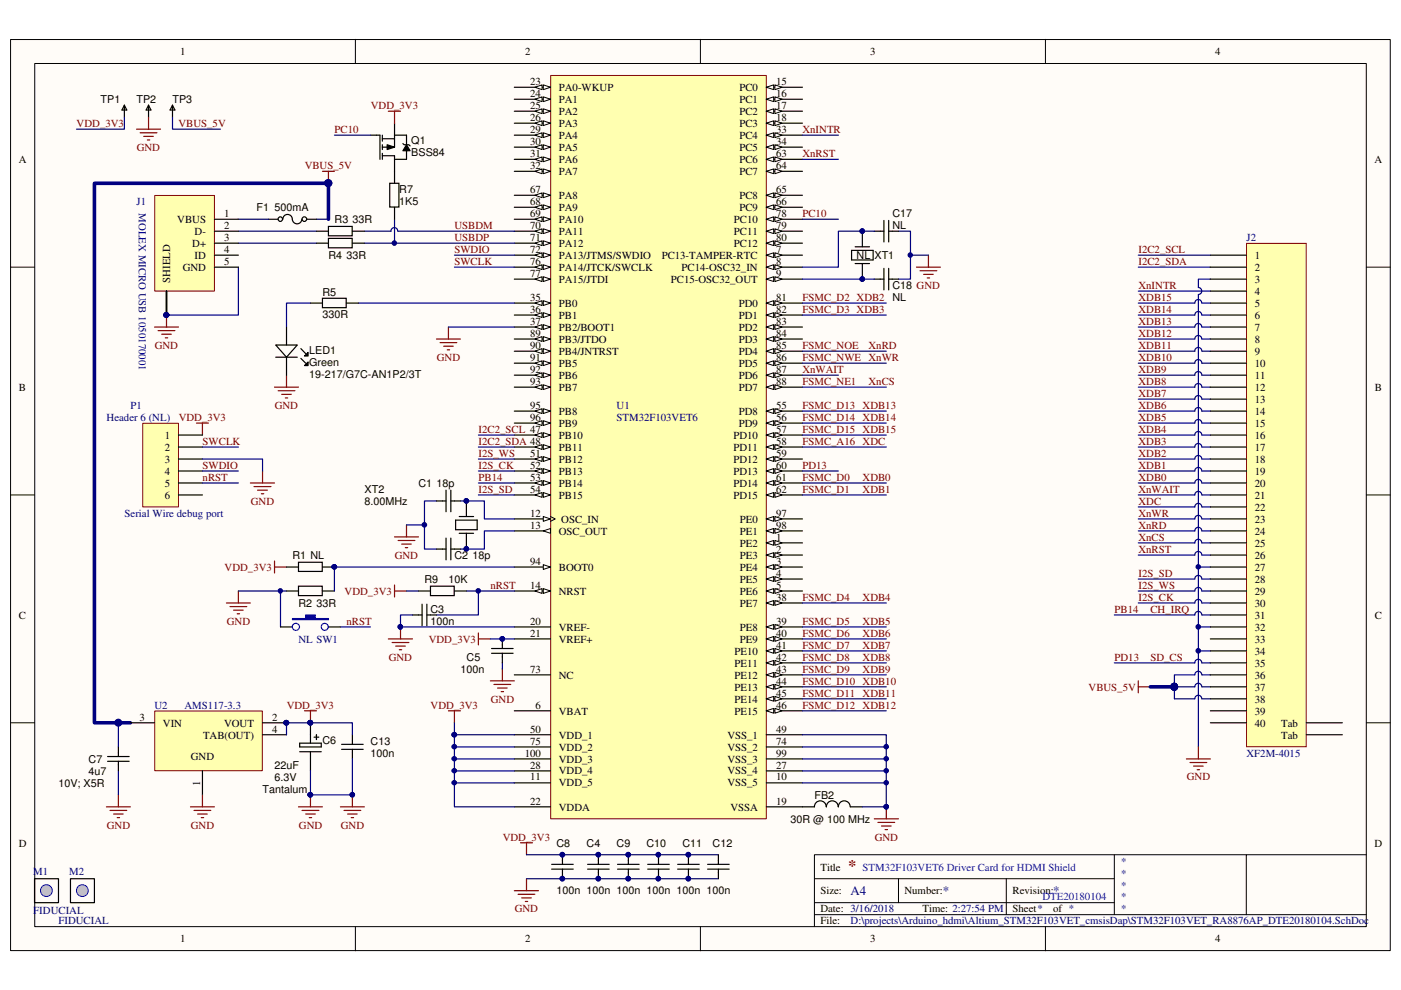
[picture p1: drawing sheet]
<svg xmlns="http://www.w3.org/2000/svg" width="297mm" height="210mm" viewBox="0 0 297 210" stroke-linecap="round" stroke-linejoin="round" font-family="sans-serif">
<defs><g id="words">
<text font-size="3.4" fill="#800000" x="179.8" y="184.6">*</text>
<g font-size="2.8" fill="#000080">
<text x="180.3" y="189.8">A4</text>
<text x="199.9" y="189.8">*</text>
<text x="223.3" y="189.8">*</text>
</g>
<g font-size="2.3">
<text x="38.2" y="11.7">1</text>
<text x="111.4" y="11.7">2</text>
<text x="184.5" y="11.7">3</text>
<text x="257.6" y="11.7">4</text>
<text x="21.3" y="21.8">TP1</text>
<text x="29" y="21.8">TP2</text>
<text x="36.6" y="21.8">TP3</text>
<text x="112.4" y="18">23</text>
<text x="112.4" y="20.6">24</text>
<text x="112.4" y="23.1">25</text>
<text x="118.5" y="19.3">PA0-WKUP</text>
<text x="118.5" y="21.8">PA1</text>
<text x="156.8" y="19.3">PC0</text>
<text x="156.8" y="21.8">PC1</text>
<text x="164.5" y="18">15</text>
<text x="164.5" y="20.6">16</text>
<text x="164.5" y="23.1">17</text>
<text x="112.4" y="25.7">26</text>
<text x="112.4" y="28.2">29</text>
<text x="118.5" y="24.4">PA2</text>
<text x="118.5" y="26.9">PA3</text>
<text x="118.5" y="29.5">PA4</text>
<text x="156.8" y="24.4">PC2</text>
<text x="156.8" y="26.9">PC3</text>
<text x="156.8" y="29.5">PC4</text>
<text x="164.5" y="25.7">18</text>
<text x="164.5" y="28.2">33</text>
<text x="4" y="34.5">A</text>
<text x="87.2" y="30.5">Q1</text>
<text x="87.2" y="33.1">BSS84</text>
<text x="112.4" y="30.7">30</text>
<text x="112.4" y="33.3">31</text>
<text x="112.4" y="35.8">32</text>
<text x="118.5" y="32">PA5</text>
<text x="118.5" y="34.5">PA6</text>
<text x="156.8" y="32">PC5</text>
<text x="156.8" y="34.5">PC6</text>
<text x="164.5" y="30.7">34</text>
<text x="164.5" y="33.3">63</text>
<text x="164.5" y="35.8">64</text>
<text x="291.4" y="34.5">A</text>
<text x="84.7" y="40.9">R7</text>
<text x="112.4" y="40.9">67</text>
<text x="118.5" y="37.1">PA7</text>
<text x="156.8" y="37.1">PC7</text>
<text x="164.5" y="40.9">65</text>
<text x="37.6" y="47.3">VBUS</text>
<text x="47.5" y="46">1</text>
<text x="54.4" y="44.7">F1</text>
<text x="58.2" y="44.7">500mA</text>
<text x="70.9" y="47.3">R3</text>
<text x="74.8" y="47.3">33R</text>
<text x="84.7" y="43.5">1K5</text>
<text x="112.4" y="43.5">68</text>
<text x="112.4" y="46">69</text>
<text x="118.5" y="42.2">PA8</text>
<text x="118.5" y="44.7">PA9</text>
<text x="118.5" y="47.3">PA10</text>
<text x="155.6" y="47.3">PC10</text>
<text x="156.8" y="42.2">PC8</text>
<text x="156.8" y="44.7">PC9</text>
<text x="164.5" y="46">78</text>
<text x="164.5" y="43.5">66</text>
<text x="189.2" y="46">C17</text>
<text x="40.8" y="52.4">D+</text>
<text x="41.3" y="49.8">D-</text>
<text x="47.5" y="48.6">2</text>
<text x="47.5" y="53.6">4</text>
<text x="47.5" y="51.1">3</text>
<text x="112.4" y="48.6">70</text>
<text x="112.4" y="51.1">71</text>
<text x="112.4" y="53.6">72</text>
<text x="118.5" y="49.8">PA11</text>
<text x="118.5" y="52.4">PA12</text>
<text x="155.6" y="49.8">PC11</text>
<text x="155.6" y="52.4">PC12</text>
<text x="164.5" y="48.6">79</text>
<text x="164.5" y="51.1">80</text>
<text x="164.5" y="53.6">7</text>
<text x="189.2" y="48.6">NL</text>
<text x="36.1" y="60" transform="rotate(-90 36.1 60)">SHIELD</text>
<text x="38.7" y="57.4">GND</text>
<text x="41.3" y="54.9">ID</text>
<text x="47.5" y="56.2">5</text>
<text x="69.6" y="54.9">R4</text>
<text x="73.5" y="54.9">33R</text>
<text x="112.4" y="56.2">76</text>
<text x="112.4" y="58.7">77</text>
<text x="118.5" y="54.9">PA13/JTMS/SWDIO</text>
<text x="118.5" y="57.4">PA14/JTCK/SWCLK</text>
<text x="118.5" y="60">PA15/JTDI</text>
<text x="140.3" y="54.9">PC13-TAMPER-RTC</text>
<text x="142.2" y="60">PC15-OSC32_OUT</text>
<text x="144.5" y="57.4">PC14-OSC32_IN</text>
<text x="164.5" y="56.2">8</text>
<text x="164.5" y="58.7">9</text>
<text x="181.6" y="54.9">NL XT1</text>
<text x="266.1" y="54.9">1</text>
<text x="266.1" y="57.4">2</text>
<text x="266.1" y="60">3</text>
<text x="68.4" y="62.8">R5</text>
<text x="112.4" y="63.8">35</text>
<text x="118.5" y="65.1">PB0</text>
<text x="156.6" y="65.1">PD0</text>
<text x="164.5" y="63.8">81</text>
<text x="189.2" y="63.8">NL</text>
<text x="189.2" y="61.3">C18 GND</text>
<text x="266.1" y="62.5">4</text>
<text x="266.1" y="65.1">5</text>
<text x="68.4" y="67.4">330R</text>
<text x="112.4" y="66.3">36</text>
<text x="112.4" y="68.9">37</text>
<text x="112.4" y="71.4">89</text>
<text x="118.5" y="67.6">PB1</text>
<text x="118.5" y="70.1">PB2/BOOT1</text>
<text x="156.6" y="67.6">PD1</text>
<text x="156.6" y="70.1">PD2</text>
<text x="164.5" y="66.3">82</text>
<text x="164.5" y="68.9">83</text>
<text x="164.5" y="71.4">84</text>
<text x="266.1" y="67.6">6</text>
<text x="266.1" y="70.1">7</text>
<text x="65.6" y="75">LED1</text>
<text x="65.6" y="77.6">Green</text>
<text x="112.4" y="74">90</text>
<text x="112.4" y="76.5">91</text>
<text x="118.5" y="72.7">PB3/JTDO</text>
<text x="118.5" y="75.2">PB4/JNTRST</text>
<text x="118.5" y="77.8">PB5</text>
<text x="156.6" y="72.7">PD3</text>
<text x="156.6" y="75.2">PD4</text>
<text x="156.6" y="77.8">PD5</text>
<text x="164.5" y="74">85</text>
<text x="164.5" y="76.5">86</text>
<text x="266.1" y="72.7">8</text>
<text x="266.1" y="75.2">9</text>
<text x="266.1" y="77.8">10</text>
<text x="4" y="82.8">B</text>
<text x="65.6" y="80.1">19-217/G7C-AN1P2/3T</text>
<text x="112.4" y="79">92</text>
<text x="112.4" y="81.6">93</text>
<text x="118.5" y="80.3">PB6</text>
<text x="118.5" y="82.8">PB7</text>
<text x="156.6" y="80.3">PD6</text>
<text x="156.6" y="82.8">PD7</text>
<text x="164.5" y="79">87</text>
<text x="164.5" y="81.6">88</text>
<text x="266.1" y="80.3">11</text>
<text x="266.1" y="82.8">12</text>
<text x="291.5" y="82.8">B</text>
<text x="112.4" y="86.7">95</text>
<text x="112.4" y="89.2">96</text>
<text x="118.5" y="88">PB8</text>
<text x="156.6" y="88">PD8</text>
<text x="164.5" y="86.7">55</text>
<text x="164.5" y="89.2">56</text>
<text x="266.1" y="85.4">13</text>
<text x="266.1" y="88">14</text>
<text x="34.9" y="93">1</text>
<text x="34.9" y="95.6">2</text>
<text x="118.5" y="90.5">PB9</text>
<text x="118.5" y="93">PB10</text>
<text x="118.5" y="95.6">PB11</text>
<text x="155.5" y="93">PD10</text>
<text x="155.5" y="95.6">PD11</text>
<text x="156.6" y="90.5">PD9</text>
<text x="164.5" y="91.8">57</text>
<text x="164.5" y="94.3">58</text>
<text x="266.1" y="90.5">15</text>
<text x="266.1" y="93">16</text>
<text x="266.1" y="95.6">17</text>
<text x="34.9" y="98.1">3</text>
<text x="34.9" y="100.7">4</text>
<text x="112.4" y="96.9">51</text>
<text x="112.4" y="99.4">52</text>
<text x="112.4" y="101.9">53</text>
<text x="118.5" y="98.1">PB12</text>
<text x="118.5" y="100.7">PB13</text>
<text x="155.5" y="98.1">PD12</text>
<text x="155.5" y="100.7">PD13</text>
<text x="164.5" y="96.9">59</text>
<text x="164.5" y="99.4">60</text>
<text x="164.5" y="101.9">61</text>
<text x="266.1" y="98.1">18</text>
<text x="266.1" y="100.7">19</text>
<text x="34.9" y="103.2">5</text>
<text x="34.9" y="105.7">6</text>
<text x="77.3" y="104.5">XT2</text>
<text x="77.3" y="107">8.00MHz</text>
<text x="88.7" y="103.2">C1</text>
<text x="92.5" y="103.2">18p</text>
<text x="112.4" y="104.5">54</text>
<text x="118.5" y="103.2">PB14</text>
<text x="118.5" y="105.7">PB15</text>
<text x="155.5" y="103.2">PD14</text>
<text x="155.5" y="105.7">PD15</text>
<text x="164.5" y="104.5">62</text>
<text x="266.1" y="103.2">20</text>
<text x="266.1" y="105.7">21</text>
<text x="112.4" y="112.1">13</text>
<text x="112.4" y="109.6">12</text>
<text x="118.5" y="113.4">OSC_OUT</text>
<text x="119" y="110.8">OSC_IN</text>
<text x="156.9" y="110.8">PE0</text>
<text x="156.9" y="113.4">PE1</text>
<text x="164.5" y="109.6">97</text>
<text x="164.5" y="112.1">98</text>
<text x="266.1" y="108.3">22</text>
<text x="266.1" y="110.8">23</text>
<text x="266.1" y="113.4">24</text>
<text x="62" y="118.5">R1 NL</text>
<text x="96.3" y="118.5">C2</text>
<text x="100.2" y="118.5">18p</text>
<text x="112.4" y="119.7">94</text>
<text x="156.9" y="115.9">PE2</text>
<text x="156.9" y="118.4">PE3</text>
<text x="164.5" y="114.6">1</text>
<text x="164.5" y="117.2">2</text>
<text x="164.5" y="119.7">3</text>
<text x="266.1" y="115.9">25</text>
<text x="266.1" y="118.4">26</text>
<text x="90" y="123.6">R9</text>
<text x="95.1" y="123.6">10K</text>
<text x="112.4" y="124.8">14</text>
<text x="118.5" y="121">BOOT0</text>
<text x="156.9" y="121">PE4</text>
<text x="156.9" y="123.5">PE5</text>
<text x="164.5" y="122.3">4</text>
<text x="164.5" y="124.8">5</text>
<text x="266.1" y="121">27</text>
<text x="266.1" y="123.5">28</text>
<text x="4" y="131.2">C</text>
<text x="63.3" y="128.7">R2</text>
<text x="67.1" y="128.7">33R</text>
<text x="91.3" y="129.9">C3</text>
<text x="118.5" y="126.1">NRST</text>
<text x="156.9" y="126.1">PE6</text>
<text x="156.9" y="128.7">PE7</text>
<text x="164.5" y="127.4">38</text>
<text x="266.1" y="126.1">29</text>
<text x="266.1" y="128.7">30</text>
<text x="266.1" y="131.2">31</text>
<text x="291.5" y="131.2">C</text>
<text x="91.3" y="132.5">100n</text>
<text x="112.4" y="132.5">20</text>
<text x="112.4" y="135">21</text>
<text x="118.5" y="133.7">VREF-</text>
<text x="118.5" y="136.3">VREF+</text>
<text x="156.9" y="133.7">PE8</text>
<text x="156.9" y="136.3">PE9</text>
<text x="164.5" y="132.5">39</text>
<text x="164.5" y="135">40</text>
<text x="164.5" y="137.5">41</text>
<text x="266.1" y="133.7">32</text>
<text x="266.1" y="136.3">33</text>
<text x="97.7" y="142.6">100n</text>
<text x="98.9" y="140.1">C5</text>
<text x="112.4" y="142.6">73</text>
<text x="118.5" y="143.9">NC</text>
<text x="155.7" y="138.8">PE10</text>
<text x="155.7" y="141.4">PE11</text>
<text x="155.7" y="143.9">PE12</text>
<text x="164.5" y="140.1">42</text>
<text x="164.5" y="142.6">43</text>
<text x="266.1" y="138.8">34</text>
<text x="266.1" y="141.4">35</text>
<text x="266.1" y="143.9">36</text>
<text x="155.7" y="146.4">PE13</text>
<text x="155.7" y="149">PE14</text>
<text x="164.5" y="145.2">44</text>
<text x="164.5" y="147.7">45</text>
<text x="266.1" y="146.4">37</text>
<text x="266.1" y="149">38</text>
<text x="29.6" y="152.8">3</text>
<text x="34.5" y="154.1">VIN</text>
<text x="47.5" y="154.1">VOUT</text>
<text x="57.7" y="152.8">2</text>
<text x="57.7" y="155.3">4</text>
<text x="112.4" y="155.3">50</text>
<text x="113.5" y="150.2">6</text>
<text x="118.5" y="151.5">VBAT</text>
<text x="155.7" y="151.5">PE15</text>
<text x="164.5" y="150.2">46</text>
<text x="164.5" y="155.3">49</text>
<text x="266.1" y="151.5">39</text>
<text x="266.1" y="154.1">40</text>
<text x="271.6" y="154.1">Tab</text>
<text x="18.8" y="161.7">C7</text>
<text x="40.5" y="161.2">GND</text>
<text x="43" y="156.6">TAB(OUT)</text>
<text x="68.4" y="157.6">C6</text>
<text x="78.6" y="160.4">100n</text>
<text x="78.6" y="157.9">C13</text>
<text x="111.2" y="160.4">100</text>
<text x="112.4" y="157.9">75</text>
<text x="118.5" y="156.6">VDD_1</text>
<text x="118.5" y="159.1">VDD_2</text>
<text x="118.5" y="161.7">VDD_3</text>
<text x="154.2" y="156.6">VSS_1</text>
<text x="154.2" y="159.1">VSS_2</text>
<text x="154.2" y="161.7">VSS_3</text>
<text x="164.5" y="157.9">74</text>
<text x="164.5" y="160.4">99</text>
<text x="271.6" y="156.6">Tab</text>
<text x="12.4" y="166.8">10V; X5R</text>
<text x="18.8" y="164.3">4u7</text>
<text x="42.5" y="166.6" transform="rotate(-90 42.5 166.6)">1</text>
<text x="58.2" y="165.5">6.3V</text>
<text x="58.2" y="163">22uF</text>
<text x="112.4" y="162.9">28</text>
<text x="112.4" y="165.5">11</text>
<text x="118.5" y="164.2">VDD_4</text>
<text x="118.5" y="166.8">VDD_5</text>
<text x="154.2" y="164.2">VSS_4</text>
<text x="154.2" y="166.8">VSS_5</text>
<text x="164.5" y="162.9">27</text>
<text x="164.5" y="165.5">10</text>
<text x="55.7" y="168.1">Tantalum</text>
<text x="112.4" y="170.6">22</text>
<text x="118.5" y="171.9">VDDA</text>
<text x="154.9" y="171.9">VSSA</text>
<text x="164.5" y="170.6">19</text>
<text x="172.7" y="169.3">FB2</text>
<text x="4" y="179.5">D</text>
<text x="118" y="179.5">C8</text>
<text x="124.4" y="179.5">C4</text>
<text x="130.7" y="179.5">C9</text>
<text x="137.1" y="179.5">C10</text>
<text x="144.7" y="179.5">C11</text>
<text x="151.1" y="179.5">C12</text>
<text x="167.6" y="174.4">30R @ 100 MHz</text>
<text x="291.4" y="179.5">D</text>
<text x="173.9" y="184.6">Title</text>
<text x="118" y="189.7">100n 100n 100n 100n 100n 100n</text>
<text x="173.9" y="189.7">Size:</text>
<text x="191.8" y="189.7">Number:</text>
<text x="214.7" y="189.7">Revision:</text>
<text x="173.9" y="193.5">Date: 3/16/2018</text>
<text x="173.9" y="196">File:</text>
<text x="195.6" y="193.5">Time: 2:27:54 PM</text>
<text x="214.7" y="193.5">Sheet*</text>
<text x="223.3" y="193.5">of *</text>
<text x="38.2" y="199.8">1</text>
<text x="111.4" y="199.8">2</text>
<text x="184.5" y="199.8">3</text>
<text x="257.6" y="199.8">4</text>
</g>
<g font-size="2.3" fill="#800000">
<text x="78.6" y="23.1">VDD_3V3</text>
<text x="16.3" y="26.9">VDD_3V3</text>
<text x="37.8" y="26.9">VBUS_5V</text>
<text x="70.9" y="28.2">PC10</text>
<text x="170.1" y="28.2">XnINTR</text>
<text x="29" y="32">GND</text>
<text x="64.6" y="35.8">VBUS_5V</text>
<text x="170.1" y="33.3">XnRST</text>
<text x="170.1" y="46">PC10</text>
<text x="96.3" y="48.6">USBDM</text>
<text x="96.3" y="51.1">USBDP</text>
<text x="96.3" y="53.6">SWDIO</text>
<text x="241.4" y="53.6">I2C2_SCL</text>
<text x="96.3" y="56.2">SWCLK</text>
<text x="241.4" y="56.2">I2C2_SDA</text>
<text x="170.1" y="63.8">FSMC_D2 XDB2</text>
<text x="241.4" y="63.8">XDB15</text>
<text x="241.4" y="61.3">XnINTR</text>
<text x="170.1" y="66.3">FSMC_D3 XDB3</text>
<text x="241.4" y="66.3">XDB14</text>
<text x="241.4" y="71.4">XDB12</text>
<text x="241.4" y="68.9">XDB13</text>
<text x="32.8" y="74">GND</text>
<text x="92.6" y="76.5">GND</text>
<text x="170.1" y="74">FSMC_NOE</text>
<text x="170.1" y="76.5">FSMC_NWE XnWR</text>
<text x="184.1" y="74">XnRD</text>
<text x="241.4" y="76.5">XDB10</text>
<text x="241.4" y="74">XDB11</text>
<text x="170.1" y="79">XnWAIT</text>
<text x="170.1" y="81.6">FSMC_NE1</text>
<text x="184.1" y="81.6">XnCS</text>
<text x="241.4" y="79">XDB9</text>
<text x="241.4" y="81.6">XDB8</text>
<text x="37.9" y="89.2">VDD_3V3</text>
<text x="58.2" y="86.7">GND</text>
<text x="170.1" y="86.7">FSMC_D13 XDB13</text>
<text x="170.1" y="89.2">FSMC_D14 XDB14</text>
<text x="241.4" y="84.1">XDB7</text>
<text x="241.4" y="86.7">XDB6</text>
<text x="241.4" y="89.2">XDB5</text>
<text x="43" y="94.3">SWCLK</text>
<text x="101.5" y="94.3">I2C2_SDA 48</text>
<text x="101.5" y="91.8">I2C2_SCL 47</text>
<text x="170.1" y="94.3">FSMC_A16 XDC</text>
<text x="170.1" y="91.8">FSMC_D15 XDB15</text>
<text x="241.4" y="91.8">XDB4</text>
<text x="241.4" y="94.3">XDB3</text>
<text x="43" y="101.9">nRST</text>
<text x="43" y="99.4">SWDIO</text>
<text x="101.5" y="99.4">I2S_CK</text>
<text x="101.5" y="96.9">I2S_WS</text>
<text x="101.5" y="101.9">PB14</text>
<text x="170.1" y="101.9">FSMC_D0</text>
<text x="170.1" y="99.4">PD13</text>
<text x="182.9" y="101.9">XDB0</text>
<text x="241.4" y="101.9">XDB0</text>
<text x="241.4" y="99.4">XDB1</text>
<text x="241.4" y="96.9">XDB2</text>
<text x="53.2" y="107">GND</text>
<text x="101.5" y="104.5">I2S_SD</text>
<text x="170.1" y="104.5">FSMC_D1</text>
<text x="182.9" y="104.5">XDB1</text>
<text x="241.4" y="104.5">XnWAIT</text>
<text x="241.4" y="107">XDC</text>
<text x="241.4" y="109.6">XnWR</text>
<text x="241.4" y="112.1">XnRD</text>
<text x="83.7" y="118.4">GND</text>
<text x="241.4" y="114.6">XnCS</text>
<text x="241.4" y="117.2">XnRST</text>
<text x="47.6" y="121">VDD_3V3</text>
<text x="104" y="124.8">nRST</text>
<text x="241.4" y="124.8">I2S_WS</text>
<text x="241.4" y="122.3">I2S_SD</text>
<text x="73.1" y="126.1">VDD_3V3</text>
<text x="170.1" y="127.4">FSMC_D4</text>
<text x="182.9" y="127.4">XDB4</text>
<text x="236.3" y="129.9">PB14</text>
<text x="241.4" y="127.4">I2S_CK</text>
<text x="243.9" y="129.9">CH_IRQ</text>
<text x="48.1" y="132.5">GND</text>
<text x="73.5" y="132.5">nRST</text>
<text x="90.9" y="136.3">VDD_3V3</text>
<text x="170.1" y="132.5">FSMC_D5</text>
<text x="170.1" y="135">FSMC_D6</text>
<text x="170.1" y="137.5">FSMC_D7</text>
<text x="182.9" y="132.5">XDB5</text>
<text x="182.9" y="135">XDB6</text>
<text x="182.9" y="137.5">XDB7</text>
<text x="82.4" y="140.1">GND</text>
<text x="170.1" y="140.1">FSMC_D8</text>
<text x="170.1" y="142.6">FSMC_D9</text>
<text x="182.9" y="140.1">XDB8</text>
<text x="182.9" y="142.6">XDB9</text>
<text x="236.3" y="140.1">PD13</text>
<text x="243.9" y="140.1">SD_CS</text>
<text x="104.1" y="149">GND</text>
<text x="170.1" y="145.2">FSMC_D10 XDB10</text>
<text x="170.1" y="147.7">FSMC_D11 XDB11</text>
<text x="230.8" y="146.4">VBUS_5V</text>
<text x="60.8" y="150.2">VDD_3V3</text>
<text x="91.3" y="150.2">VDD_3V3</text>
<text x="170.1" y="150.2">FSMC_D12 XDB12</text>
<text x="251.6" y="165.5">GND</text>
<text x="22.6" y="175.7">GND</text>
<text x="40.5" y="175.7">GND</text>
<text x="63.4" y="175.7">GND</text>
<text x="72.3" y="175.7">GND</text>
<text x="106.6" y="178.2">VDD_3V3</text>
<text x="185.5" y="178.2">GND</text>
<text x="109.1" y="193.5">GND</text>
</g>
<g font-size="2.3" fill="#000080">
<text x="29" y="43.5">J1</text>
<text x="29.5" y="45.2" transform="rotate(90 29.5 45.2)">MOLEX MICRO USB 1050170001</text>
<text x="264.3" y="51.1">J2</text>
<text x="22.6" y="89.2">Header 6 (NL)</text>
<text x="27.7" y="86.7">P1</text>
<text x="130.7" y="86.7">U1</text>
<text x="130.7" y="89.2">STM32F103VET6</text>
<text x="26.4" y="109.6">Serial Wire debug port</text>
<text x="63.3" y="136.3">NL SW1</text>
<text x="32.8" y="150.2">U2</text>
<text x="39.1" y="150.2">AMS117-3.3</text>
<text x="264.3" y="160.4">XF2M-4015</text>
<text x="7.1" y="185.6">M1</text>
<text x="14.7" y="185.6">M2</text>
<text x="237.6" y="183.3">*</text>
<text x="237.6" y="185.8">*</text>
<text x="237.6" y="188.4">*</text>
<text x="237.6" y="190.9">*</text>
<text x="7.1" y="193.7">FIDUCIAL</text>
<text x="12.4" y="196">FIDUCIAL</text>
<text x="180.3" y="196">D:\projects\Arduino_hdmi\Altium_STM32F103VET_cmsisDap\STM32F103VET_RA8876AP_DTE20180104.SchDoc</text>
<text x="237.6" y="193.5">*</text>
</g>
<g font-size="2.3" fill="#00f">
<text x="182.9" y="184.6">STM32F103VET6 Driver Card for HDMI Shield</text>
<text x="221" y="190.9">DTE20180104</text>
</g>
</g></defs>
<path d="M2.3 8.4h292.5v193.1h-292.5z" fill="#fffcf8"/>
<path d="M2.2 8.4h292.6v193.1h-292.6z" fill="none" stroke="#000" stroke-width=".21"/>
<path d="M7.4 13.5h282.3v183h-282.3z" fill="#fffcf8"/>
<g fill="none" stroke="#000" stroke-width=".21">
<path d="M7.4 13.5h282.3v183h-282.3zM75.3 8.3v5.1M148.5 8.3v5.1M221.7 8.3v5.1M2.2 56.6h5.1M289.7 56.6h5.1M2.2 104.9h5.1M289.7 104.9h5.1M2.2 153.2h5.1M289.7 153.2h5.1M75.3 196.5v5.1M148.5 196.5v5.1"/>
<path d="M172.7 186.3h63.6M172.7 193.9h117M172.7 191.4h63.6M190.5 186.3v5.1M213.4 186.3v7.6M221.7 196.5v5.1M236.3 181.2v12.7M264.2 181.2h-91.5v15.3M289.7 181.2h-25.5v12.7"/>
</g>
<path d="M116.8 16h45.7v157.6h-45.7z" fill="#ffffb0"/>
<path d="M116.8 16h45.7v157.6h-45.7z" fill="none" stroke="#800000" stroke-width=".21"/>
<path d="M109 120.2h7.7" fill="none" stroke="#000" stroke-width=".25"/>
<path d="M115.2 119.7l1.5 .5-1.5 .5z" fill="#fffcf8"/>
<path d="M115.2 119.7l1.5 .5-1.5 .5z" fill="none" stroke="#000" stroke-width=".21"/>
<path d="M109 125.3h7.7M109 143.1h7.7" fill="none" stroke="#000" stroke-width=".25"/>
<path d="M115.2 124.8l1.5 .5-1.5 .5z" fill="#fffcf8"/>
<path d="M115.2 124.8l1.5 .5-1.5 .5z" fill="none" stroke="#000" stroke-width=".21"/>
<path d="M113.4 125.3l1.5-.5v1z" fill="#fffcf8"/>
<path d="M116.7 109.5l1 .5-1 .5M113.4 125.3l1.5-.5v1z" fill="none" stroke="#000" stroke-width=".21"/>
<path d="M109 110h7.7" fill="none" stroke="#000" stroke-width=".25"/>
<path d="M115.2 109.5l1.5 .5-1.5 .5z" fill="#fffcf8"/>
<path d="M115.2 109.5l1.5 .5-1.5 .5z" fill="none" stroke="#000" stroke-width=".21"/>
<path d="M109 112.6h7.7" fill="none" stroke="#000" stroke-width=".25"/>
<path d="M115.2 112.6l1.5-.5v1z" fill="#fffcf8"/>
<path d="M115.2 112.6l1.5-.5v1z" fill="none" stroke="#000" stroke-width=".21"/>
<path d="M109 18.5h7.7" fill="none" stroke="#000" stroke-width=".25"/>
<path d="M115.2 18l1.5 .5-1.5 .5z" fill="#fffcf8"/>
<path d="M115.2 18l1.5 .5-1.5 .5z" fill="none" stroke="#000" stroke-width=".21"/>
<path d="M113.4 18.5l1.5-.5v1z" fill="#fffcf8"/>
<path d="M113.4 18.5l1.5-.5v1z" fill="none" stroke="#000" stroke-width=".21"/>
<path d="M109 21h7.7" fill="none" stroke="#000" stroke-width=".25"/>
<path d="M115.2 20.5l1.5 .5-1.5 .5z" fill="#fffcf8"/>
<path d="M115.2 20.5l1.5 .5-1.5 .5z" fill="none" stroke="#000" stroke-width=".21"/>
<path d="M113.4 21l1.5-.5v1z" fill="#fffcf8"/>
<path d="M113.4 21l1.5-.5v1z" fill="none" stroke="#000" stroke-width=".21"/>
<path d="M109 23.6h7.7" fill="none" stroke="#000" stroke-width=".25"/>
<path d="M115.2 23.1l1.5 .5-1.5 .5z" fill="#fffcf8"/>
<path d="M115.2 23.1l1.5 .5-1.5 .5z" fill="none" stroke="#000" stroke-width=".21"/>
<path d="M113.4 23.6l1.5-.5v1z" fill="#fffcf8"/>
<path d="M113.4 23.6l1.5-.5v1z" fill="none" stroke="#000" stroke-width=".21"/>
<path d="M109 26.1h7.7" fill="none" stroke="#000" stroke-width=".25"/>
<path d="M115.2 25.6l1.5 .5-1.5 .5z" fill="#fffcf8"/>
<path d="M115.2 25.6l1.5 .5-1.5 .5z" fill="none" stroke="#000" stroke-width=".21"/>
<path d="M113.4 26.1l1.5-.5v1z" fill="#fffcf8"/>
<path d="M113.4 26.1l1.5-.5v1z" fill="none" stroke="#000" stroke-width=".21"/>
<path d="M109 28.7h7.7" fill="none" stroke="#000" stroke-width=".25"/>
<path d="M115.2 28.2l1.5 .5-1.5 .5z" fill="#fffcf8"/>
<path d="M115.2 28.2l1.5 .5-1.5 .5z" fill="none" stroke="#000" stroke-width=".21"/>
<path d="M113.4 28.7l1.5-.5v1z" fill="#fffcf8"/>
<path d="M113.4 28.7l1.5-.5v1z" fill="none" stroke="#000" stroke-width=".21"/>
<path d="M109 31.2h7.7" fill="none" stroke="#000" stroke-width=".25"/>
<path d="M115.2 30.7l1.5 .5-1.5 .5z" fill="#fffcf8"/>
<path d="M115.2 30.7l1.5 .5-1.5 .5z" fill="none" stroke="#000" stroke-width=".21"/>
<path d="M113.4 31.2l1.5-.5v1z" fill="#fffcf8"/>
<path d="M113.4 31.2l1.5-.5v1z" fill="none" stroke="#000" stroke-width=".21"/>
<path d="M109 33.8h7.7" fill="none" stroke="#000" stroke-width=".25"/>
<path d="M115.2 33.3l1.5 .5-1.5 .5z" fill="#fffcf8"/>
<path d="M115.2 33.3l1.5 .5-1.5 .5z" fill="none" stroke="#000" stroke-width=".21"/>
<path d="M113.4 33.8l1.5-.5v1z" fill="#fffcf8"/>
<path d="M113.4 33.8l1.5-.5v1z" fill="none" stroke="#000" stroke-width=".21"/>
<path d="M109 36.3h7.7" fill="none" stroke="#000" stroke-width=".25"/>
<path d="M115.2 35.8l1.5 .5-1.5 .5z" fill="#fffcf8"/>
<path d="M115.2 35.8l1.5 .5-1.5 .5z" fill="none" stroke="#000" stroke-width=".21"/>
<path d="M113.4 36.3l1.5-.5v1z" fill="#fffcf8"/>
<path d="M113.4 36.3l1.5-.5v1z" fill="none" stroke="#000" stroke-width=".21"/>
<path d="M109 41.4h7.7" fill="none" stroke="#000" stroke-width=".25"/>
<path d="M115.2 40.9l1.5 .5-1.5 .5z" fill="#fffcf8"/>
<path d="M115.2 40.9l1.5 .5-1.5 .5z" fill="none" stroke="#000" stroke-width=".21"/>
<path d="M113.4 41.4l1.5-.5v1z" fill="#fffcf8"/>
<path d="M113.4 41.4l1.5-.5v1z" fill="none" stroke="#000" stroke-width=".21"/>
<path d="M109 43.9h7.7" fill="none" stroke="#000" stroke-width=".25"/>
<path d="M115.2 43.4l1.5 .5-1.5 .5z" fill="#fffcf8"/>
<path d="M115.2 43.4l1.5 .5-1.5 .5z" fill="none" stroke="#000" stroke-width=".21"/>
<path d="M113.4 43.9l1.5-.5v1z" fill="#fffcf8"/>
<path d="M113.4 43.9l1.5-.5v1z" fill="none" stroke="#000" stroke-width=".21"/>
<path d="M109 46.5h7.7" fill="none" stroke="#000" stroke-width=".25"/>
<path d="M115.2 46l1.5 .5-1.5 .5z" fill="#fffcf8"/>
<path d="M115.2 46l1.5 .5-1.5 .5z" fill="none" stroke="#000" stroke-width=".21"/>
<path d="M113.4 46.5l1.5-.5v1z" fill="#fffcf8"/>
<path d="M113.4 46.5l1.5-.5v1z" fill="none" stroke="#000" stroke-width=".21"/>
<path d="M109 49h7.7" fill="none" stroke="#000" stroke-width=".25"/>
<path d="M115.2 48.5l1.5 .5-1.5 .5z" fill="#fffcf8"/>
<path d="M115.2 48.5l1.5 .5-1.5 .5z" fill="none" stroke="#000" stroke-width=".21"/>
<path d="M113.4 49l1.5-.5v1z" fill="#fffcf8"/>
<path d="M113.4 49l1.5-.5v1z" fill="none" stroke="#000" stroke-width=".21"/>
<path d="M109 51.6h7.7" fill="none" stroke="#000" stroke-width=".25"/>
<path d="M115.2 51.1l1.5 .5-1.5 .5z" fill="#fffcf8"/>
<path d="M115.2 51.1l1.5 .5-1.5 .5z" fill="none" stroke="#000" stroke-width=".21"/>
<path d="M113.4 51.6l1.5-.5v1z" fill="#fffcf8"/>
<path d="M113.4 51.6l1.5-.5v1z" fill="none" stroke="#000" stroke-width=".21"/>
<path d="M109 54.1h7.7" fill="none" stroke="#000" stroke-width=".25"/>
<path d="M115.2 53.6l1.5 .5-1.5 .5z" fill="#fffcf8"/>
<path d="M115.2 53.6l1.5 .5-1.5 .5z" fill="none" stroke="#000" stroke-width=".21"/>
<path d="M113.4 54.1l1.5-.5v1z" fill="#fffcf8"/>
<path d="M113.4 54.1l1.5-.5v1z" fill="none" stroke="#000" stroke-width=".21"/>
<path d="M109 56.6h7.7" fill="none" stroke="#000" stroke-width=".25"/>
<path d="M115.2 56.1l1.5 .5-1.5 .5z" fill="#fffcf8"/>
<path d="M115.2 56.1l1.5 .5-1.5 .5z" fill="none" stroke="#000" stroke-width=".21"/>
<path d="M113.4 56.6l1.5-.5v1z" fill="#fffcf8"/>
<path d="M113.4 56.6l1.5-.5v1z" fill="none" stroke="#000" stroke-width=".21"/>
<path d="M109 59.2h7.7" fill="none" stroke="#000" stroke-width=".25"/>
<path d="M115.2 58.7l1.5 .5-1.5 .5z" fill="#fffcf8"/>
<path d="M115.2 58.7l1.5 .5-1.5 .5z" fill="none" stroke="#000" stroke-width=".21"/>
<path d="M113.4 59.2l1.5-.5v1z" fill="#fffcf8"/>
<path d="M113.4 59.2l1.5-.5v1z" fill="none" stroke="#000" stroke-width=".21"/>
<path d="M109 64.3h7.7" fill="none" stroke="#000" stroke-width=".25"/>
<path d="M115.2 63.8l1.5 .5-1.5 .5z" fill="#fffcf8"/>
<path d="M115.2 63.8l1.5 .5-1.5 .5z" fill="none" stroke="#000" stroke-width=".21"/>
<path d="M113.4 64.3l1.5-.5v1z" fill="#fffcf8"/>
<path d="M113.4 64.3l1.5-.5v1z" fill="none" stroke="#000" stroke-width=".21"/>
<path d="M109 66.8h7.7" fill="none" stroke="#000" stroke-width=".25"/>
<path d="M115.2 66.3l1.5 .5-1.5 .5z" fill="#fffcf8"/>
<path d="M115.2 66.3l1.5 .5-1.5 .5z" fill="none" stroke="#000" stroke-width=".21"/>
<path d="M113.4 66.8l1.5-.5v1z" fill="#fffcf8"/>
<path d="M113.4 66.8l1.5-.5v1z" fill="none" stroke="#000" stroke-width=".21"/>
<path d="M109 69.3h7.7" fill="none" stroke="#000" stroke-width=".25"/>
<path d="M115.2 68.8l1.5 .5-1.5 .5z" fill="#fffcf8"/>
<path d="M115.2 68.8l1.5 .5-1.5 .5z" fill="none" stroke="#000" stroke-width=".21"/>
<path d="M113.4 69.3l1.5-.5v1z" fill="#fffcf8"/>
<path d="M113.4 69.3l1.5-.5v1z" fill="none" stroke="#000" stroke-width=".21"/>
<path d="M109 71.9h7.7" fill="none" stroke="#000" stroke-width=".25"/>
<path d="M115.2 71.4l1.5 .5-1.5 .5z" fill="#fffcf8"/>
<path d="M115.2 71.4l1.5 .5-1.5 .5z" fill="none" stroke="#000" stroke-width=".21"/>
<path d="M113.4 71.9l1.5-.5v1z" fill="#fffcf8"/>
<path d="M113.4 71.9l1.5-.5v1z" fill="none" stroke="#000" stroke-width=".21"/>
<path d="M109 74.5h7.7" fill="none" stroke="#000" stroke-width=".25"/>
<path d="M115.2 73.9l1.5 .6-1.5 .5z" fill="#fffcf8"/>
<path d="M115.2 73.9l1.5 .6-1.5 .5z" fill="none" stroke="#000" stroke-width=".21"/>
<path d="M113.4 74.5l1.5-.6v1.1z" fill="#fffcf8"/>
<path d="M113.4 74.5l1.5-.6v1.1z" fill="none" stroke="#000" stroke-width=".21"/>
<path d="M109 77h7.7" fill="none" stroke="#000" stroke-width=".25"/>
<path d="M115.2 76.5l1.5 .5-1.5 .5z" fill="#fffcf8"/>
<path d="M115.2 76.5l1.5 .5-1.5 .5z" fill="none" stroke="#000" stroke-width=".21"/>
<path d="M113.4 77l1.5-.5v1z" fill="#fffcf8"/>
<path d="M113.4 77l1.5-.5v1z" fill="none" stroke="#000" stroke-width=".21"/>
<path d="M109 79.5h7.7" fill="none" stroke="#000" stroke-width=".25"/>
<path d="M115.2 79l1.5 .5-1.5 .6z" fill="#fffcf8"/>
<path d="M115.2 79l1.5 .5-1.5 .6z" fill="none" stroke="#000" stroke-width=".21"/>
<path d="M113.4 79.5l1.5-.5v1.1z" fill="#fffcf8"/>
<path d="M113.4 79.5l1.5-.5v1.1z" fill="none" stroke="#000" stroke-width=".21"/>
<path d="M109 82.1h7.7" fill="none" stroke="#000" stroke-width=".25"/>
<path d="M115.2 81.6l1.5 .5-1.5 .5z" fill="#fffcf8"/>
<path d="M115.2 81.6l1.5 .5-1.5 .5z" fill="none" stroke="#000" stroke-width=".21"/>
<path d="M113.4 82.1l1.5-.5v1z" fill="#fffcf8"/>
<path d="M113.4 82.1l1.5-.5v1z" fill="none" stroke="#000" stroke-width=".21"/>
<path d="M109 87.2h7.7" fill="none" stroke="#000" stroke-width=".25"/>
<path d="M115.2 86.7l1.5 .5-1.5 .5z" fill="#fffcf8"/>
<path d="M115.2 86.7l1.5 .5-1.5 .5z" fill="none" stroke="#000" stroke-width=".21"/>
<path d="M113.4 87.2l1.5-.5v1z" fill="#fffcf8"/>
<path d="M113.4 87.2l1.5-.5v1z" fill="none" stroke="#000" stroke-width=".21"/>
<path d="M109 89.7h7.7" fill="none" stroke="#000" stroke-width=".25"/>
<path d="M115.2 89.2l1.5 .5-1.5 .5z" fill="#fffcf8"/>
<path d="M115.2 89.2l1.5 .5-1.5 .5z" fill="none" stroke="#000" stroke-width=".21"/>
<path d="M113.4 89.7l1.5-.5v1z" fill="#fffcf8"/>
<path d="M113.4 89.7l1.5-.5v1z" fill="none" stroke="#000" stroke-width=".21"/>
<path d="M109 92.2h7.7" fill="none" stroke="#000" stroke-width=".25"/>
<path d="M115.2 91.7l1.5 .5-1.5 .6z" fill="#fffcf8"/>
<path d="M115.2 91.7l1.5 .5-1.5 .6z" fill="none" stroke="#000" stroke-width=".21"/>
<path d="M113.4 92.2l1.5-.5v1.1z" fill="#fffcf8"/>
<path d="M113.4 92.2l1.5-.5v1.1z" fill="none" stroke="#000" stroke-width=".21"/>
<path d="M109 94.8h7.7" fill="none" stroke="#000" stroke-width=".25"/>
<path d="M115.2 94.3l1.5 .5-1.5 .5z" fill="#fffcf8"/>
<path d="M115.2 94.3l1.5 .5-1.5 .5z" fill="none" stroke="#000" stroke-width=".21"/>
<path d="M113.4 94.8l1.5-.5v1z" fill="#fffcf8"/>
<path d="M113.4 94.8l1.5-.5v1z" fill="none" stroke="#000" stroke-width=".21"/>
<path d="M109 97.3h7.7" fill="none" stroke="#000" stroke-width=".25"/>
<path d="M115.2 96.8l1.5 .5-1.5 .5z" fill="#fffcf8"/>
<path d="M115.2 96.8l1.5 .5-1.5 .5z" fill="none" stroke="#000" stroke-width=".21"/>
<path d="M113.4 97.3l1.5-.5v1z" fill="#fffcf8"/>
<path d="M113.4 97.3l1.5-.5v1z" fill="none" stroke="#000" stroke-width=".21"/>
<path d="M109 99.9h7.7" fill="none" stroke="#000" stroke-width=".25"/>
<path d="M115.2 99.4l1.5 .5-1.5 .5z" fill="#fffcf8"/>
<path d="M115.2 99.4l1.5 .5-1.5 .5z" fill="none" stroke="#000" stroke-width=".21"/>
<path d="M113.4 99.9l1.5-.5v1z" fill="#fffcf8"/>
<path d="M113.4 99.9l1.5-.5v1z" fill="none" stroke="#000" stroke-width=".21"/>
<path d="M109 102.4h7.7" fill="none" stroke="#000" stroke-width=".25"/>
<path d="M115.2 101.9l1.5 .5-1.5 .5z" fill="#fffcf8"/>
<path d="M115.2 101.9l1.5 .5-1.5 .5z" fill="none" stroke="#000" stroke-width=".21"/>
<path d="M113.4 102.4l1.5-.5v1z" fill="#fffcf8"/>
<path d="M113.4 102.4l1.5-.5v1z" fill="none" stroke="#000" stroke-width=".21"/>
<path d="M109 104.9h7.7" fill="none" stroke="#000" stroke-width=".25"/>
<path d="M115.2 104.4l1.5 .5-1.5 .6z" fill="#fffcf8"/>
<path d="M115.2 104.4l1.5 .5-1.5 .6z" fill="none" stroke="#000" stroke-width=".21"/>
<path d="M113.4 104.9l1.5-.5v1.1z" fill="#fffcf8"/>
<path d="M113.4 104.9l1.5-.5v1.1z" fill="none" stroke="#000" stroke-width=".21"/>
<path d="M162.5 18.5h7.6" fill="none" stroke="#000" stroke-width=".25"/>
<path d="M162.5 18.5l1.5-.5v1z" fill="#fffcf8"/>
<path d="M162.5 18.5l1.5-.5v1z" fill="none" stroke="#000" stroke-width=".21"/>
<path d="M164.3 18l1.5 .5-1.5 .5z" fill="#fffcf8"/>
<path d="M164.3 18l1.5 .5-1.5 .5z" fill="none" stroke="#000" stroke-width=".21"/>
<path d="M162.5 21h7.6" fill="none" stroke="#000" stroke-width=".25"/>
<path d="M162.5 21l1.5-.5v1z" fill="#fffcf8"/>
<path d="M162.5 21l1.5-.5v1z" fill="none" stroke="#000" stroke-width=".21"/>
<path d="M164.3 20.5l1.5 .5-1.5 .5z" fill="#fffcf8"/>
<path d="M164.3 20.5l1.5 .5-1.5 .5z" fill="none" stroke="#000" stroke-width=".21"/>
<path d="M162.5 23.6h7.6" fill="none" stroke="#000" stroke-width=".25"/>
<path d="M162.5 23.6l1.5-.5v1z" fill="#fffcf8"/>
<path d="M162.5 23.6l1.5-.5v1z" fill="none" stroke="#000" stroke-width=".21"/>
<path d="M164.3 23.1l1.5 .5-1.5 .5z" fill="#fffcf8"/>
<path d="M164.3 23.1l1.5 .5-1.5 .5z" fill="none" stroke="#000" stroke-width=".21"/>
<path d="M162.5 26.1h7.6" fill="none" stroke="#000" stroke-width=".25"/>
<path d="M162.5 26.1l1.5-.5v1z" fill="#fffcf8"/>
<path d="M162.5 26.1l1.5-.5v1z" fill="none" stroke="#000" stroke-width=".21"/>
<path d="M164.3 25.6l1.5 .5-1.5 .5z" fill="#fffcf8"/>
<path d="M164.3 25.6l1.5 .5-1.5 .5z" fill="none" stroke="#000" stroke-width=".21"/>
<path d="M162.5 28.7h7.6" fill="none" stroke="#000" stroke-width=".25"/>
<path d="M162.5 28.7l1.5-.5v1z" fill="#fffcf8"/>
<path d="M162.5 28.7l1.5-.5v1z" fill="none" stroke="#000" stroke-width=".21"/>
<path d="M164.3 28.2l1.5 .5-1.5 .5z" fill="#fffcf8"/>
<path d="M164.3 28.2l1.5 .5-1.5 .5z" fill="none" stroke="#000" stroke-width=".21"/>
<path d="M162.5 31.2h7.6" fill="none" stroke="#000" stroke-width=".25"/>
<path d="M162.5 31.2l1.5-.5v1z" fill="#fffcf8"/>
<path d="M162.5 31.2l1.5-.5v1z" fill="none" stroke="#000" stroke-width=".21"/>
<path d="M164.3 30.7l1.5 .5-1.5 .5z" fill="#fffcf8"/>
<path d="M164.3 30.7l1.5 .5-1.5 .5z" fill="none" stroke="#000" stroke-width=".21"/>
<path d="M162.5 33.8h7.6" fill="none" stroke="#000" stroke-width=".25"/>
<path d="M162.5 33.8l1.5-.5v1z" fill="#fffcf8"/>
<path d="M162.5 33.8l1.5-.5v1z" fill="none" stroke="#000" stroke-width=".21"/>
<path d="M164.3 33.3l1.5 .5-1.5 .5z" fill="#fffcf8"/>
<path d="M164.3 33.3l1.5 .5-1.5 .5z" fill="none" stroke="#000" stroke-width=".21"/>
<path d="M162.5 36.3h7.6" fill="none" stroke="#000" stroke-width=".25"/>
<path d="M162.5 36.3l1.5-.5v1z" fill="#fffcf8"/>
<path d="M162.5 36.3l1.5-.5v1z" fill="none" stroke="#000" stroke-width=".21"/>
<path d="M164.3 35.8l1.5 .5-1.5 .5z" fill="#fffcf8"/>
<path d="M164.3 35.8l1.5 .5-1.5 .5z" fill="none" stroke="#000" stroke-width=".21"/>
<path d="M162.5 41.4h7.6" fill="none" stroke="#000" stroke-width=".25"/>
<path d="M162.5 41.4l1.5-.5v1z" fill="#fffcf8"/>
<path d="M162.5 41.4l1.5-.5v1z" fill="none" stroke="#000" stroke-width=".21"/>
<path d="M164.3 40.9l1.5 .5-1.5 .5z" fill="#fffcf8"/>
<path d="M164.3 40.9l1.5 .5-1.5 .5z" fill="none" stroke="#000" stroke-width=".21"/>
<path d="M162.5 43.9h7.6" fill="none" stroke="#000" stroke-width=".25"/>
<path d="M162.5 43.9l1.5-.5v1z" fill="#fffcf8"/>
<path d="M162.5 43.9l1.5-.5v1z" fill="none" stroke="#000" stroke-width=".21"/>
<path d="M164.3 43.4l1.5 .5-1.5 .5z" fill="#fffcf8"/>
<path d="M164.3 43.4l1.5 .5-1.5 .5z" fill="none" stroke="#000" stroke-width=".21"/>
<path d="M162.5 46.5h7.6" fill="none" stroke="#000" stroke-width=".25"/>
<path d="M162.5 46.5l1.5-.5v1z" fill="#fffcf8"/>
<path d="M162.5 46.5l1.5-.5v1z" fill="none" stroke="#000" stroke-width=".21"/>
<path d="M164.3 46l1.5 .5-1.5 .5z" fill="#fffcf8"/>
<path d="M164.3 46l1.5 .5-1.5 .5z" fill="none" stroke="#000" stroke-width=".21"/>
<path d="M162.5 49h7.6" fill="none" stroke="#000" stroke-width=".25"/>
<path d="M162.5 49l1.5-.5v1z" fill="#fffcf8"/>
<path d="M162.5 49l1.5-.5v1z" fill="none" stroke="#000" stroke-width=".21"/>
<path d="M164.3 48.5l1.5 .5-1.5 .5z" fill="#fffcf8"/>
<path d="M164.3 48.5l1.5 .5-1.5 .5z" fill="none" stroke="#000" stroke-width=".21"/>
<path d="M162.5 51.6h7.6" fill="none" stroke="#000" stroke-width=".25"/>
<path d="M162.5 51.6l1.5-.5v1z" fill="#fffcf8"/>
<path d="M162.5 51.6l1.5-.5v1z" fill="none" stroke="#000" stroke-width=".21"/>
<path d="M164.3 51.1l1.5 .5-1.5 .5z" fill="#fffcf8"/>
<path d="M164.3 51.1l1.5 .5-1.5 .5z" fill="none" stroke="#000" stroke-width=".21"/>
<path d="M162.5 54.1h7.6" fill="none" stroke="#000" stroke-width=".25"/>
<path d="M162.5 54.1l1.5-.5v1z" fill="#fffcf8"/>
<path d="M162.5 54.1l1.5-.5v1z" fill="none" stroke="#000" stroke-width=".21"/>
<path d="M164.3 53.6l1.5 .5-1.5 .5z" fill="#fffcf8"/>
<path d="M164.3 53.6l1.5 .5-1.5 .5z" fill="none" stroke="#000" stroke-width=".21"/>
<path d="M162.5 56.6h7.6" fill="none" stroke="#000" stroke-width=".25"/>
<path d="M162.5 56.6l1.5-.5v1z" fill="#fffcf8"/>
<path d="M162.5 56.6l1.5-.5v1z" fill="none" stroke="#000" stroke-width=".21"/>
<path d="M164.3 56.1l1.5 .5-1.5 .5z" fill="#fffcf8"/>
<path d="M164.3 56.1l1.5 .5-1.5 .5z" fill="none" stroke="#000" stroke-width=".21"/>
<path d="M162.5 59.2h7.6" fill="none" stroke="#000" stroke-width=".25"/>
<path d="M162.5 59.2l1.5-.5v1z" fill="#fffcf8"/>
<path d="M162.5 59.2l1.5-.5v1z" fill="none" stroke="#000" stroke-width=".21"/>
<path d="M164.3 58.7l1.5 .5-1.5 .5z" fill="#fffcf8"/>
<path d="M164.3 58.7l1.5 .5-1.5 .5z" fill="none" stroke="#000" stroke-width=".21"/>
<path d="M162.5 64.3h7.6" fill="none" stroke="#000" stroke-width=".25"/>
<path d="M162.5 64.3l1.5-.5v1z" fill="#fffcf8"/>
<path d="M162.5 64.3l1.5-.5v1z" fill="none" stroke="#000" stroke-width=".21"/>
<path d="M164.3 63.8l1.5 .5-1.5 .5z" fill="#fffcf8"/>
<path d="M164.3 63.8l1.5 .5-1.5 .5z" fill="none" stroke="#000" stroke-width=".21"/>
<path d="M162.5 66.8h7.6" fill="none" stroke="#000" stroke-width=".25"/>
<path d="M162.5 66.8l1.5-.5v1z" fill="#fffcf8"/>
<path d="M162.5 66.8l1.5-.5v1z" fill="none" stroke="#000" stroke-width=".21"/>
<path d="M164.3 66.3l1.5 .5-1.5 .5z" fill="#fffcf8"/>
<path d="M164.3 66.3l1.5 .5-1.5 .5z" fill="none" stroke="#000" stroke-width=".21"/>
<path d="M162.5 69.3h7.6" fill="none" stroke="#000" stroke-width=".25"/>
<path d="M162.5 69.3l1.5-.5v1z" fill="#fffcf8"/>
<path d="M162.5 69.3l1.5-.5v1z" fill="none" stroke="#000" stroke-width=".21"/>
<path d="M164.3 68.8l1.5 .5-1.5 .5z" fill="#fffcf8"/>
<path d="M164.3 68.8l1.5 .5-1.5 .5z" fill="none" stroke="#000" stroke-width=".21"/>
<path d="M162.5 71.9h7.6" fill="none" stroke="#000" stroke-width=".25"/>
<path d="M162.5 71.9l1.5-.5v1z" fill="#fffcf8"/>
<path d="M162.5 71.9l1.5-.5v1z" fill="none" stroke="#000" stroke-width=".21"/>
<path d="M164.3 71.4l1.5 .5-1.5 .5z" fill="#fffcf8"/>
<path d="M164.3 71.4l1.5 .5-1.5 .5z" fill="none" stroke="#000" stroke-width=".21"/>
<path d="M162.5 74.5h7.6" fill="none" stroke="#000" stroke-width=".25"/>
<path d="M162.5 74.5l1.5-.6v1.1z" fill="#fffcf8"/>
<path d="M162.5 74.5l1.5-.6v1.1z" fill="none" stroke="#000" stroke-width=".21"/>
<path d="M164.3 73.9l1.5 .6-1.5 .5z" fill="#fffcf8"/>
<path d="M164.3 73.9l1.5 .6-1.5 .5z" fill="none" stroke="#000" stroke-width=".21"/>
<path d="M162.5 77h7.6" fill="none" stroke="#000" stroke-width=".25"/>
<path d="M162.5 77l1.5-.5v1z" fill="#fffcf8"/>
<path d="M162.5 77l1.5-.5v1z" fill="none" stroke="#000" stroke-width=".21"/>
<path d="M164.3 76.5l1.5 .5-1.5 .5z" fill="#fffcf8"/>
<path d="M164.3 76.5l1.5 .5-1.5 .5z" fill="none" stroke="#000" stroke-width=".21"/>
<path d="M162.5 79.5h7.6" fill="none" stroke="#000" stroke-width=".25"/>
<path d="M162.5 79.5l1.5-.5v1.1z" fill="#fffcf8"/>
<path d="M162.5 79.5l1.5-.5v1.1z" fill="none" stroke="#000" stroke-width=".21"/>
<path d="M164.3 79l1.5 .5-1.5 .6z" fill="#fffcf8"/>
<path d="M164.3 79l1.5 .5-1.5 .6z" fill="none" stroke="#000" stroke-width=".21"/>
<path d="M162.5 82.1h7.6" fill="none" stroke="#000" stroke-width=".25"/>
<path d="M162.5 82.1l1.5-.5v1z" fill="#fffcf8"/>
<path d="M162.5 82.1l1.5-.5v1z" fill="none" stroke="#000" stroke-width=".21"/>
<path d="M164.3 81.6l1.5 .5-1.5 .5z" fill="#fffcf8"/>
<path d="M164.3 81.6l1.5 .5-1.5 .5z" fill="none" stroke="#000" stroke-width=".21"/>
<path d="M162.5 87.2h7.6" fill="none" stroke="#000" stroke-width=".25"/>
<path d="M162.5 87.2l1.5-.5v1z" fill="#fffcf8"/>
<path d="M162.5 87.2l1.5-.5v1z" fill="none" stroke="#000" stroke-width=".21"/>
<path d="M164.3 86.7l1.5 .5-1.5 .5z" fill="#fffcf8"/>
<path d="M164.3 86.7l1.5 .5-1.5 .5z" fill="none" stroke="#000" stroke-width=".21"/>
<path d="M162.5 89.7h7.6" fill="none" stroke="#000" stroke-width=".25"/>
<path d="M162.5 89.7l1.5-.5v1z" fill="#fffcf8"/>
<path d="M162.5 89.7l1.5-.5v1z" fill="none" stroke="#000" stroke-width=".21"/>
<path d="M164.3 89.2l1.5 .5-1.5 .5z" fill="#fffcf8"/>
<path d="M164.3 89.2l1.5 .5-1.5 .5z" fill="none" stroke="#000" stroke-width=".21"/>
<path d="M162.5 92.2h7.6" fill="none" stroke="#000" stroke-width=".25"/>
<path d="M162.5 92.2l1.5-.5v1.1z" fill="#fffcf8"/>
<path d="M162.5 92.2l1.5-.5v1.1z" fill="none" stroke="#000" stroke-width=".21"/>
<path d="M164.3 91.7l1.5 .5-1.5 .6z" fill="#fffcf8"/>
<path d="M164.3 91.7l1.5 .5-1.5 .6z" fill="none" stroke="#000" stroke-width=".21"/>
<path d="M162.5 94.8h7.6" fill="none" stroke="#000" stroke-width=".25"/>
<path d="M162.5 94.8l1.5-.5v1z" fill="#fffcf8"/>
<path d="M162.5 94.8l1.5-.5v1z" fill="none" stroke="#000" stroke-width=".21"/>
<path d="M164.3 94.3l1.5 .5-1.5 .5z" fill="#fffcf8"/>
<path d="M164.3 94.3l1.5 .5-1.5 .5z" fill="none" stroke="#000" stroke-width=".21"/>
<path d="M162.5 97.3h7.6" fill="none" stroke="#000" stroke-width=".25"/>
<path d="M162.5 97.3l1.5-.5v1z" fill="#fffcf8"/>
<path d="M162.5 97.3l1.5-.5v1z" fill="none" stroke="#000" stroke-width=".21"/>
<path d="M164.3 96.8l1.5 .5-1.5 .5z" fill="#fffcf8"/>
<path d="M164.3 96.8l1.5 .5-1.5 .5z" fill="none" stroke="#000" stroke-width=".21"/>
<path d="M162.5 99.9h7.6" fill="none" stroke="#000" stroke-width=".25"/>
<path d="M162.5 99.9l1.5-.5v1z" fill="#fffcf8"/>
<path d="M162.5 99.9l1.5-.5v1z" fill="none" stroke="#000" stroke-width=".21"/>
<path d="M164.3 99.4l1.5 .5-1.5 .5z" fill="#fffcf8"/>
<path d="M164.3 99.4l1.5 .5-1.5 .5z" fill="none" stroke="#000" stroke-width=".21"/>
<path d="M162.5 102.4h7.6" fill="none" stroke="#000" stroke-width=".25"/>
<path d="M162.5 102.4l1.5-.5v1z" fill="#fffcf8"/>
<path d="M162.5 102.4l1.5-.5v1z" fill="none" stroke="#000" stroke-width=".21"/>
<path d="M164.3 101.9l1.5 .5-1.5 .5z" fill="#fffcf8"/>
<path d="M164.3 101.9l1.5 .5-1.5 .5z" fill="none" stroke="#000" stroke-width=".21"/>
<path d="M162.5 104.9h7.6" fill="none" stroke="#000" stroke-width=".25"/>
<path d="M162.5 104.9l1.5-.5v1.1z" fill="#fffcf8"/>
<path d="M162.5 104.9l1.5-.5v1.1z" fill="none" stroke="#000" stroke-width=".21"/>
<path d="M164.3 104.4l1.5 .5-1.5 .6z" fill="#fffcf8"/>
<path d="M164.3 104.4l1.5 .5-1.5 .6z" fill="none" stroke="#000" stroke-width=".21"/>
<path d="M162.5 110h7.6" fill="none" stroke="#000" stroke-width=".25"/>
<path d="M162.5 110l1.5-.5v1z" fill="#fffcf8"/>
<path d="M162.5 110l1.5-.5v1z" fill="none" stroke="#000" stroke-width=".21"/>
<path d="M164.3 109.5l1.5 .5-1.5 .5z" fill="#fffcf8"/>
<path d="M164.3 109.5l1.5 .5-1.5 .5z" fill="none" stroke="#000" stroke-width=".21"/>
<path d="M162.5 112.6h7.6" fill="none" stroke="#000" stroke-width=".25"/>
<path d="M162.5 112.6l1.5-.5v1z" fill="#fffcf8"/>
<path d="M162.5 112.6l1.5-.5v1z" fill="none" stroke="#000" stroke-width=".21"/>
<path d="M164.3 112.1l1.5 .5-1.5 .5z" fill="#fffcf8"/>
<path d="M164.3 112.1l1.5 .5-1.5 .5z" fill="none" stroke="#000" stroke-width=".21"/>
<path d="M162.5 115.1h7.6" fill="none" stroke="#000" stroke-width=".25"/>
<path d="M162.5 115.1l1.5-.5v1z" fill="#fffcf8"/>
<path d="M162.5 115.1l1.5-.5v1z" fill="none" stroke="#000" stroke-width=".21"/>
<path d="M164.3 114.6l1.5 .5-1.5 .5z" fill="#fffcf8"/>
<path d="M164.3 114.6l1.5 .5-1.5 .5z" fill="none" stroke="#000" stroke-width=".21"/>
<path d="M162.5 117.7h7.6" fill="none" stroke="#000" stroke-width=".25"/>
<path d="M162.5 117.7l1.5-.5v1z" fill="#fffcf8"/>
<path d="M162.5 117.7l1.5-.5v1z" fill="none" stroke="#000" stroke-width=".21"/>
<path d="M164.3 117.2l1.5 .5-1.5 .5z" fill="#fffcf8"/>
<path d="M164.3 117.2l1.5 .5-1.5 .5z" fill="none" stroke="#000" stroke-width=".21"/>
<path d="M162.5 120.2h7.6" fill="none" stroke="#000" stroke-width=".25"/>
<path d="M162.5 120.2l1.5-.5v1z" fill="#fffcf8"/>
<path d="M162.5 120.2l1.5-.5v1z" fill="none" stroke="#000" stroke-width=".21"/>
<path d="M164.3 119.7l1.5 .5-1.5 .5z" fill="#fffcf8"/>
<path d="M164.3 119.7l1.5 .5-1.5 .5z" fill="none" stroke="#000" stroke-width=".21"/>
<path d="M162.5 122.8h7.6" fill="none" stroke="#000" stroke-width=".25"/>
<path d="M162.5 122.8l1.5-.5v1z" fill="#fffcf8"/>
<path d="M162.5 122.8l1.5-.5v1z" fill="none" stroke="#000" stroke-width=".21"/>
<path d="M164.3 122.3l1.5 .5-1.5 .5z" fill="#fffcf8"/>
<path d="M164.3 122.3l1.5 .5-1.5 .5z" fill="none" stroke="#000" stroke-width=".21"/>
<path d="M162.5 125.3h7.6" fill="none" stroke="#000" stroke-width=".25"/>
<path d="M162.5 125.3l1.5-.5v1z" fill="#fffcf8"/>
<path d="M162.5 125.3l1.5-.5v1z" fill="none" stroke="#000" stroke-width=".21"/>
<path d="M164.3 124.8l1.5 .5-1.5 .5z" fill="#fffcf8"/>
<path d="M164.3 124.8l1.5 .5-1.5 .5z" fill="none" stroke="#000" stroke-width=".21"/>
<path d="M162.5 127.8h7.6" fill="none" stroke="#000" stroke-width=".25"/>
<path d="M162.5 127.8l1.5-.5v1.1z" fill="#fffcf8"/>
<path d="M162.5 127.8l1.5-.5v1.1z" fill="none" stroke="#000" stroke-width=".21"/>
<path d="M164.3 127.3l1.5 .5-1.5 .6z" fill="#fffcf8"/>
<path d="M164.3 127.3l1.5 .5-1.5 .6z" fill="none" stroke="#000" stroke-width=".21"/>
<path d="M162.5 132.9h7.6" fill="none" stroke="#000" stroke-width=".25"/>
<path d="M162.5 132.9l1.5-.5v1z" fill="#fffcf8"/>
<path d="M162.5 132.9l1.5-.5v1z" fill="none" stroke="#000" stroke-width=".21"/>
<path d="M164.3 132.4l1.5 .5-1.5 .5z" fill="#fffcf8"/>
<path d="M164.3 132.4l1.5 .5-1.5 .5z" fill="none" stroke="#000" stroke-width=".21"/>
<path d="M162.5 135.5h7.6" fill="none" stroke="#000" stroke-width=".25"/>
<path d="M162.5 135.5l1.5-.5v1z" fill="#fffcf8"/>
<path d="M162.5 135.5l1.5-.5v1z" fill="none" stroke="#000" stroke-width=".21"/>
<path d="M164.3 135l1.5 .5-1.5 .5z" fill="#fffcf8"/>
<path d="M164.3 135l1.5 .5-1.5 .5z" fill="none" stroke="#000" stroke-width=".21"/>
<path d="M162.5 138h7.6" fill="none" stroke="#000" stroke-width=".25"/>
<path d="M162.5 138l1.5-.5v1z" fill="#fffcf8"/>
<path d="M162.5 138l1.5-.5v1z" fill="none" stroke="#000" stroke-width=".21"/>
<path d="M164.3 137.5l1.5 .5-1.5 .5z" fill="#fffcf8"/>
<path d="M164.3 137.5l1.5 .5-1.5 .5z" fill="none" stroke="#000" stroke-width=".21"/>
<path d="M162.5 140.5h7.6" fill="none" stroke="#000" stroke-width=".25"/>
<path d="M162.5 140.5l1.5-.5v1.1z" fill="#fffcf8"/>
<path d="M162.5 140.5l1.5-.5v1.1z" fill="none" stroke="#000" stroke-width=".21"/>
<path d="M164.3 140l1.5 .5-1.5 .6z" fill="#fffcf8"/>
<path d="M164.3 140l1.5 .5-1.5 .6z" fill="none" stroke="#000" stroke-width=".21"/>
<path d="M162.5 143.1h7.6" fill="none" stroke="#000" stroke-width=".25"/>
<path d="M162.5 143.1l1.5-.5v1z" fill="#fffcf8"/>
<path d="M162.5 143.1l1.5-.5v1z" fill="none" stroke="#000" stroke-width=".21"/>
<path d="M164.3 142.6l1.5 .5-1.5 .5z" fill="#fffcf8"/>
<path d="M164.3 142.6l1.5 .5-1.5 .5z" fill="none" stroke="#000" stroke-width=".21"/>
<path d="M162.5 145.6h7.6" fill="none" stroke="#000" stroke-width=".25"/>
<path d="M162.5 145.6l1.5-.5v1z" fill="#fffcf8"/>
<path d="M162.5 145.6l1.5-.5v1z" fill="none" stroke="#000" stroke-width=".21"/>
<path d="M164.3 145.1l1.5 .5-1.5 .5z" fill="#fffcf8"/>
<path d="M164.3 145.1l1.5 .5-1.5 .5z" fill="none" stroke="#000" stroke-width=".21"/>
<path d="M162.5 148.2h7.6" fill="none" stroke="#000" stroke-width=".25"/>
<path d="M162.5 148.2l1.5-.5v1z" fill="#fffcf8"/>
<path d="M162.5 148.2l1.5-.5v1z" fill="none" stroke="#000" stroke-width=".21"/>
<path d="M164.3 147.7l1.5 .5-1.5 .5z" fill="#fffcf8"/>
<path d="M164.3 147.7l1.5 .5-1.5 .5z" fill="none" stroke="#000" stroke-width=".21"/>
<path d="M162.5 150.7h7.6" fill="none" stroke="#000" stroke-width=".25"/>
<path d="M162.5 150.7l1.5-.5v1z" fill="#fffcf8"/>
<path d="M162.5 150.7l1.5-.5v1z" fill="none" stroke="#000" stroke-width=".21"/>
<path d="M164.3 150.2l1.5 .5-1.5 .5z" fill="#fffcf8"/>
<path d="M164.3 150.2l1.5 .5-1.5 .5z" fill="none" stroke="#000" stroke-width=".21"/>
<g fill="none" stroke="#000" stroke-width=".25">
<path d="M109 132.9h7.7M109 135.5h7.7M109 155.8h7.7M109 158.4h7.7M109 150.7h7.7M162.5 155.8h7.6M162.5 158.4h7.6M109 160.9h7.7M109 163.4h7.7M109 166h7.7M109 171.1h7.7M162.5 160.9h7.6"/>
<path d="M162.5 163.4h7.6M162.5 166h7.6M162.5 171.1h7.6"/>
</g>
<path d="M58.2 119v2.5M48 127.8h5.1M48.8 128.6h3.5M49.5 129.4h2.1M50.3 130.1h.5M50.5 125.3v2.5M58.2 120.2h2.5M185.4 173.6h5.1M186.1 174.4h3.6M186.9 175.1h2M187.7 175.9h.5M187.9 171.1v2.5" fill="none" stroke="#800000" stroke-width=".25"/>
<path d="M170.1 79.5h7.7" fill="none" stroke="#000080" stroke-width=".25"/>
<circle cx="187.9" cy="171" r=".48" fill="#000080"/>
<circle cx="187.9" cy="171" r=".48" fill="none" stroke="#000080" stroke-width=".21"/>
<path d="M170.1 158.4h17.8" fill="none" stroke="#000080" stroke-width=".25"/>
<circle cx="187.9" cy="158.3" r=".48" fill="#000080"/>
<circle cx="187.9" cy="158.3" r=".48" fill="none" stroke="#000080" stroke-width=".21"/>
<path d="M170.1 160.9h17.8" fill="none" stroke="#000080" stroke-width=".25"/>
<circle cx="187.9" cy="160.9" r=".48" fill="#000080"/>
<circle cx="187.9" cy="160.9" r=".48" fill="none" stroke="#000080" stroke-width=".21"/>
<path d="M170.1 163.4h17.8" fill="none" stroke="#000080" stroke-width=".25"/>
<circle cx="187.9" cy="163.4" r=".48" fill="#000080"/>
<circle cx="187.9" cy="163.4" r=".48" fill="none" stroke="#000080" stroke-width=".21"/>
<path d="M170.1 166h17.8" fill="none" stroke="#000080" stroke-width=".25"/>
<circle cx="187.9" cy="165.9" r=".48" fill="#000080"/>
<circle cx="187.9" cy="165.9" r=".48" fill="none" stroke="#000080" stroke-width=".21"/>
<path d="M96.3 166h12.7" fill="none" stroke="#000080" stroke-width=".25"/>
<circle cx="96.3" cy="165.9" r=".48" fill="#000080"/>
<circle cx="96.3" cy="165.9" r=".48" fill="none" stroke="#000080" stroke-width=".21"/>
<path d="M96.3 160.9h12.7" fill="none" stroke="#000080" stroke-width=".25"/>
<circle cx="96.3" cy="160.9" r=".48" fill="#000080"/>
<circle cx="96.3" cy="160.9" r=".48" fill="none" stroke="#000080" stroke-width=".21"/>
<path d="M96.3 158.4h12.7" fill="none" stroke="#000080" stroke-width=".25"/>
<circle cx="96.3" cy="158.3" r=".49" fill="#000080"/>
<circle cx="96.3" cy="158.3" r=".49" fill="none" stroke="#000080" stroke-width=".21"/>
<path d="M96.3 163.4h12.7" fill="none" stroke="#000080" stroke-width=".25"/>
<circle cx="96.3" cy="163.4" r=".48" fill="#000080"/>
<circle cx="96.3" cy="163.4" r=".48" fill="none" stroke="#000080" stroke-width=".21"/>
<g fill="none" stroke="#800000" stroke-width=".25">
<path d="M68.4 36.3h2.5M69.6 36.3v2.6M83.6 113.8h5.1M84.4 114.6h3.6M85.2 115.4h2M85.9 116.1h.5M86.2 111.3v2.5M95.1 150.7h2.5M96.3 150.7v2.5M110.4 178.7h2.5M111.6 178.7v2.5M109 188.8h5.2"/>
<path d="M109.9 189.6h3.5M110.6 190.4h2M111.4 191.1h.5M111.6 186.3v2.5"/>
</g>
<path d="M97.6 106.2h5.1v3.8h6.3M109 112.6h-6.3v3.8h-5.1" fill="none" stroke="#000080" stroke-width=".25"/>
<circle cx="69.6" cy="38.8" r=".75" fill="#000080"/>
<circle cx="69.6" cy="38.8" r=".75" fill="none" stroke="#000080" stroke-width=".21"/>
<path d="M78.5 28.7h2.1v5.1M81.1 33h2.5v3.3M81.1 29.4h2.5M81.1 28.7v1.2M81.1 30.7v1M81.1 32.5v1.3M82.1 30.7l1.5 .5-1.5 .5zM83.6 26.1v5.1h-2.5M83.6 28.7h2.6v2M85.4 30.4l.3 .3h1l.2 .2M86.2 30.7l.7 1.3h-1.5zM86.2 32v1.8h-2.6" fill="none" stroke="#000" stroke-width=".25"/>
<path d="M82.1 30.7l1.5 .5-1.5 .5zM86.2 30.7l.7 1.3h-1.5z" fill="#000"/>
<path d="M82.3 23.6h2.6M83.6 23.6v2.5" fill="none" stroke="#800000" stroke-width=".25"/>
<path d="M70.9 28.7h7.6M83.6 46.5v5.1" fill="none" stroke="#000080" stroke-width=".25"/>
<circle cx="83.6" cy="51.5" r=".48" fill="#000080"/>
<circle cx="83.6" cy="51.5" r=".48" fill="none" stroke="#000080" stroke-width=".21"/>
<path d="M64.6 150.7h2.5M65.8 150.7v2.5" fill="none" stroke="#800000" stroke-width=".25"/>
<circle cx="65.8" cy="153.2" r=".49" fill="#000080"/>
<circle cx="65.8" cy="153.2" r=".49" fill="none" stroke="#000080" stroke-width=".21"/>
<path d="M109 155.8h-12.7v15.3h12.7" fill="none" stroke="#000080" stroke-width=".25"/>
<circle cx="96.3" cy="155.8" r=".49" fill="#000080"/>
<circle cx="96.3" cy="155.8" r=".49" fill="none" stroke="#000080" stroke-width=".21"/>
<path d="M96.3 153.2v2.6" fill="none" stroke="#000080" stroke-width=".25"/>
<circle cx="96.3" cy="155.8" r=".49" fill="#000080"/>
<circle cx="96.3" cy="155.8" r=".49" fill="none" stroke="#000080" stroke-width=".21"/>
<path d="M50.5 56.6v10.2h-15.2" fill="none" stroke="#000080" stroke-width=".25"/>
<circle cx="35.3" cy="66.8" r=".49" fill="#000080"/>
<circle cx="35.3" cy="66.8" r=".49" fill="none" stroke="#000080" stroke-width=".21"/>
<path d="M32.8 69.3h5M33.5 70.1h3.6M34.3 70.9h2M35 71.6h.6M35.3 66.8v2.5" fill="none" stroke="#800000" stroke-width=".25"/>
<circle cx="35.3" cy="66.8" r=".49" fill="#000080"/>
<circle cx="35.3" cy="66.8" r=".49" fill="none" stroke="#000080" stroke-width=".21"/>
<path d="M82.3 135.5h5.2M83.1 136.2h3.6M83.9 137h2M84.7 137.8h.5M84.9 132.9v2.6" fill="none" stroke="#800000" stroke-width=".25"/>
<circle cx="84.9" cy="132.9" r=".48" fill="#000080"/>
<circle cx="84.9" cy="132.9" r=".48" fill="none" stroke="#000080" stroke-width=".21"/>
<g fill="none" stroke="#800000" stroke-width=".25">
<path d="M60.7 79.5v2.6M92.5 71.9h5.1M93.3 72.6h3.6M94.1 73.4h2M94.8 74.2h.5M95.1 69.3v2.6M41.7 89.7h2.5M42.9 89.7v2.5M58.2 82.1h5.1M59 82.8h3.5M59.7 83.6h2.1M60.5 84.4h.5"/>
<path d="M101.4 134.2v2.5M101.4 135.5h2.6M104 144.4h5M104.7 145.1h3.6M105.5 145.9h2M106.3 146.6h.5M106.5 141.8v2.6"/>
</g>
<path d="M96.3 54.1h12.7M96.3 56.6h12.7M65.8 64.3h-5.1v5M76 64.3h33M95.1 69.3h13.9M104 135.5h5" fill="none" stroke="#000080" stroke-width=".25"/>
<path d="M182.8 55.9v3.3" fill="none" stroke="#000" stroke-width=".25"/>
<circle cx="182.8" cy="59.2" r=".49" fill="#000080"/>
<circle cx="182.8" cy="59.2" r=".49" fill="none" stroke="#000080" stroke-width=".21"/>
<path d="M182.8 49v3.3" fill="none" stroke="#000" stroke-width=".25"/>
<circle cx="182.8" cy="49" r=".49" fill="#000080"/>
<circle cx="182.8" cy="49" r=".49" fill="none" stroke="#000080" stroke-width=".21"/>
<path d="M180.5 53.1h4.6v2h-4.6zM181.3 52.3h3.1M181.3 55.9h3.1" fill="none" stroke="#000" stroke-width=".25"/>
<circle cx="182.8" cy="59.2" r=".49" fill="#000080"/>
<circle cx="182.8" cy="59.2" r=".49" fill="none" stroke="#000080" stroke-width=".21"/>
<circle cx="182.8" cy="49" r=".49" fill="#000080"/>
<circle cx="182.8" cy="49" r=".49" fill="none" stroke="#000080" stroke-width=".21"/>
<path d="M190.5 49h2.5v10.2h-2.5M193 54.1h3.8" fill="none" stroke="#000080" stroke-width=".25"/>
<path d="M194.3 56.6h5.1M195.1 57.4h3.5M195.8 58.2h2.1M196.6 58.9h.5M196.8 54.1v2.5" fill="none" stroke="#800000" stroke-width=".25"/>
<circle cx="193" cy="54.1" r=".48" fill="#000080"/>
<circle cx="193" cy="54.1" r=".48" fill="none" stroke="#000080" stroke-width=".21"/>
<path d="M86.2 111.3h3.8M92.5 106.2h-2.5v10.2h2.5" fill="none" stroke="#000080" stroke-width=".25"/>
<circle cx="90" cy="111.3" r=".49" fill="#000080"/>
<circle cx="90" cy="111.3" r=".49" fill="none" stroke="#000080" stroke-width=".21"/>
<g fill="none" stroke="#000080" stroke-width=".25">
<path d="M26.4 24.8v2.6h-10.2M36.6 24.8v2.6h10.1M170.1 64.3h17.8M170.1 66.8h17.8M170.1 77h17.8M170.1 74.5h17.8M101.4 94.8h7.6M101.4 92.2h7.6M170.1 94.8h17.8M170.1 87.2h17.8M170.1 89.7h17.8M170.1 92.2h17.8"/>
<path d="M170.1 82.1h17.8M170.1 102.4h17.8M170.1 104.9h17.8M50.5 125.3h10.2M98.9 125.3h10.1M101.4 125.3v5.1h-8.9M106.5 140.5v1.3M170.1 140.5h17.8M170.1 143.1h17.8M170.1 145.6h17.8M170.1 148.2h17.8M170.1 150.7h17.8"/>
</g>
<path d="M26.4 22.3v2.5M26.4 22.3l.5 1h-1zM31.5 22.3l.5 1h-1zM31.5 22.3v2.5M36.6 22.3l.5 1h-1zM36.6 22.3v2.5" fill="none" stroke="#000" stroke-width=".25"/>
<path d="M29 27.4h5M29.7 28.2h3.6M30.5 28.9h2M31.2 29.7h.5M31.5 24.8v2.6" fill="none" stroke="#800000" stroke-width=".25"/>
<circle cx="101.4" cy="125.3" r=".49" fill="#000080"/>
<circle cx="101.4" cy="125.3" r=".49" fill="none" stroke="#000080" stroke-width=".21"/>
<path d="M83.6 124v2.6M83.6 125.3h2.6" fill="none" stroke="#800000" stroke-width=".25"/>
<path d="M59.5 125.3v7.6M86.2 125.3h2.5" fill="none" stroke="#000080" stroke-width=".25"/>
<circle cx="59.4" cy="125.3" r=".47" fill="#000080"/>
<circle cx="59.4" cy="125.3" r=".47" fill="none" stroke="#000080" stroke-width=".21"/>
<path d="M50.5 49h16.6M50.5 51.6h16.6M67.1 46.5h2.5M77.3 49h5.6a.72 .72 0 0 1 .7-.7 .72 .72 0 0 1 .7 .7M77.3 51.6h31.7M84.4 49h24.6M101.4 97.3h7.6M101.4 99.9h7.6M101.4 104.9h7.6M72.2 132.9h6.3" fill="none" stroke="#000080" stroke-width=".25"/>
<circle cx="9.8" cy="188.8" r="1.25" fill="#c0c0c0"/>
<circle cx="9.8" cy="188.8" r="1.25" fill="none" stroke="#00f" stroke-width=".21"/>
<path d="M7.3 186.3h5.1v5.1h-5.1z" fill="none" stroke="#000" stroke-width=".25"/>
<circle cx="17.5" cy="188.8" r="1.25" fill="#c0c0c0"/>
<circle cx="17.5" cy="188.8" r="1.25" fill="none" stroke="#00f" stroke-width=".21"/>
<path d="M98.9 113.1v3.3M14.9 186.3h5.1v5.1h-5.1z" fill="none" stroke="#000" stroke-width=".25"/>
<circle cx="98.9" cy="116.4" r=".49" fill="#000080"/>
<circle cx="98.9" cy="116.4" r=".49" fill="none" stroke="#000080" stroke-width=".21"/>
<path d="M98.9 106.2v3.3" fill="none" stroke="#000" stroke-width=".25"/>
<circle cx="98.9" cy="106.2" r=".49" fill="#000080"/>
<circle cx="98.9" cy="106.2" r=".49" fill="none" stroke="#000080" stroke-width=".21"/>
<path d="M96.6 110.3h4.6v2h-4.6zM97.4 109.5h3M97.4 113.1h3" fill="none" stroke="#000" stroke-width=".25"/>
<circle cx="98.9" cy="116.4" r=".49" fill="#000080"/>
<circle cx="98.9" cy="116.4" r=".49" fill="none" stroke="#000080" stroke-width=".21"/>
<circle cx="98.9" cy="106.2" r=".49" fill="#000080"/>
<circle cx="98.9" cy="106.2" r=".49" fill="none" stroke="#000080" stroke-width=".21"/>
<g fill="none" stroke="#000080" stroke-width=".25">
<path d="M256.6 59.2h-2.5v1.8a.74 .74 0 0 1 .7 .7 .74 .74 0 0 1-.7 .7M241.3 64.3h12a.74 .74 0 0 1 .8-.8 .74 .74 0 0 1 .7 .8M241.3 66.8h12a.74 .74 0 0 1 .8-.8 .74 .74 0 0 1 .7 .8M241.3 69.3h12a.74 .74 0 0 1 .8-.7 .74 .74 0 0 1 .7 .7M241.3 71.9h12a.74 .74 0 0 1 .8-.8 .74 .74 0 0 1 .7 .8M241.3 77h12a.74 .74 0 0 1 .8-.8 .74 .74 0 0 1 .7 .8M241.3 79.5h12a.74 .74 0 0 1 .8-.7 .74 .74 0 0 1 .7 .7M241.3 61.7h15.3M254.1 62.5v95.9M254.8 74.4a.74 .74 0 0 0-.8-.7 .74 .74 0 0 0-.7 .8h-12M254.8 64.3h1.8M254.8 66.8h1.8"/>
<path d="M254.8 69.3h1.8M254.8 71.9h1.8M254.8 74.5h1.8M254.8 77h1.8M254.8 79.5h1.8M241.3 82.1h12a.74 .74 0 0 1 .8-.8 .74 .74 0 0 1 .7 .8M241.3 84.6h12a.74 .74 0 0 1 .8-.7 .74 .74 0 0 1 .7 .7M241.3 92.2h12a.74 .74 0 0 1 .8-.7 .74 .74 0 0 1 .7 .7M241.3 94.8h12a.74 .74 0 0 1 .8-.8 .74 .74 0 0 1 .7 .8M241.3 97.3h12a.74 .74 0 0 1 .8-.7 .74 .74 0 0 1 .7 .7M241.3 99.9h12a.74 .74 0 0 1 .8-.8 .74 .74 0 0 1 .7 .8M254.8 82.1h1.8"/>
<path d="M254.8 84.6h1.8M254.8 92.2h1.8M254.8 94.8h1.8M254.8 97.3h1.8M254.8 99.9h1.8M241.3 102.4h12a.74 .74 0 0 1 .8-.8 .74 .74 0 0 1 .7 .8M241.3 104.9h12a.74 .74 0 0 1 .8-.7 .74 .74 0 0 1 .7 .7M241.3 107.5h12a.74 .74 0 0 1 .8-.8 .74 .74 0 0 1 .7 .8M241.3 110h12a.74 .74 0 0 1 .8-.7 .74 .74 0 0 1 .7 .7M241.3 112.6h12a.74 .74 0 0 1 .8-.8 .74 .74 0 0 1 .7 .8M241.3 115.1h12a.74 .74 0 0 1 .7-.8 .74 .74 0 0 1 .8 .8M241.3 117.7h12a.74 .74 0 0 1 .8-.8 .74 .74 0 0 1 .7 .8"/>
<path d="M254.8 102.4h1.8M254.8 104.9h1.8M254.8 107.5h1.8M254.8 110h1.8M254.8 112.6h1.8M254.8 115.1h1.8M254.8 117.7h1.8M254.1 120.2h2.5"/>
</g>
<path d="M254.1 158.4v2.5M251.5 160.9h5.1M252.3 161.7h3.6M253.1 162.4h2M253.8 163.2h.5" fill="none" stroke="#800000" stroke-width=".25"/>
<circle cx="254.1" cy="120.2" r=".48" fill="#000080"/>
<circle cx="254.1" cy="120.2" r=".48" fill="none" stroke="#000080" stroke-width=".21"/>
<path d="M241.3 122.8h12a.74 .74 0 0 1 .8-.8 .74 .74 0 0 1 .7 .8M241.3 125.3h12a.74 .74 0 0 1 .8-.8 .74 .74 0 0 1 .7 .8M241.3 127.8h12a.74 .74 0 0 1 .8-.7 .74 .74 0 0 1 .7 .7M254.1 132.9h2.5M254.8 122.8h1.8M254.8 125.3h1.8M254.8 127.8h1.8" fill="none" stroke="#000080" stroke-width=".25"/>
<circle cx="254.1" cy="132.9" r=".49" fill="#000080"/>
<circle cx="254.1" cy="132.9" r=".49" fill="none" stroke="#000080" stroke-width=".21"/>
<path d="M254.1 138h2.5" fill="none" stroke="#000080" stroke-width=".25"/>
<circle cx="254.1" cy="138" r=".49" fill="#000080"/>
<circle cx="254.1" cy="138" r=".49" fill="none" stroke="#000080" stroke-width=".21"/>
<path d="M170.1 127.8h17.8M170.1 132.9h17.8M170.1 135.5h17.8M170.1 138h17.8M249 148.2h4.3a.74 .74 0 0 1 .8-.8 .74 .74 0 0 1 .7 .8M254.8 143.1a.74 .74 0 0 0-.7-.8 .74 .74 0 0 0-.8 .8h-4.3v2.5M254.8 148.2h1.8M254.8 143.1h1.8" fill="none" stroke="#000080" stroke-width=".25"/>
<path d="M241.3 144.4v2.5M241.3 145.6h2.6" fill="none" stroke="#800000" stroke-width=".25"/>
<circle cx="248.9" cy="145.6" r=".73" fill="#000080"/>
<circle cx="248.9" cy="145.6" r=".73" fill="none" stroke="#000080" stroke-width=".21"/>
<path d="M249 145.6h4.3a.74 .74 0 0 1 .8-.7 .74 .74 0 0 1 .7 .7M254.8 145.6h1.8" fill="none" stroke="#000080" stroke-width=".25"/>
<circle cx="248.9" cy="145.6" r=".73" fill="#000080"/>
<circle cx="248.9" cy="145.6" r=".73" fill="none" stroke="#000080" stroke-width=".21"/>
<path d="M249 145.6v2.6" fill="none" stroke="#000080" stroke-width=".25"/>
<circle cx="248.9" cy="145.6" r=".73" fill="#000080"/>
<circle cx="248.9" cy="145.6" r=".73" fill="none" stroke="#000080" stroke-width=".21"/>
<path d="M243.9 145.6h5.1" fill="none" stroke="#000080" stroke-width=".76"/>
<circle cx="248.9" cy="145.6" r=".73" fill="#000080"/>
<circle cx="248.9" cy="145.6" r=".73" fill="none" stroke="#000080" stroke-width=".21"/>
<g fill="none" stroke="#000" stroke-width=".25">
<path d="M56.9 46.5h2.1M60 46.5a1 1 0 0 1 1-1 1 1 0 0 1 1 1 1.02 1.02 0 0 0 1 1 1.02 1.02 0 0 0 1-1M65.1 46.5h2"/>
<circle cx="59.4" cy="46.5" r=".48"/>
<circle cx="64.5" cy="46.5" r=".49"/>
</g>
<path d="M50.5 46.5h6.4" fill="none" stroke="#000080" stroke-width=".25"/>
<path d="M32.8 41.5h12.7v20.2h-12.7z" fill="#ffffb0"/>
<path d="M32.8 41.4h12.7v20.3h-12.7z" fill="none" stroke="#800000" stroke-width=".21"/>
<path d="M45.5 46.5h5M45.5 49h5M45.5 51.6h5M45.5 54.1h5M45.5 56.6h5M35.3 61.7v5.1" fill="none" stroke="#000" stroke-width=".25"/>
<circle cx="35.3" cy="66.8" r=".49" fill="#000080"/>
<circle cx="35.3" cy="66.8" r=".49" fill="none" stroke="#000080" stroke-width=".21"/>
<path d="M35.3 61.7v5.1" fill="none" stroke="#000" stroke-width=".25"/>
<circle cx="35.3" cy="66.8" r=".49" fill="#000080"/>
<circle cx="35.3" cy="66.8" r=".49" fill="none" stroke="#000080" stroke-width=".21"/>
<path d="M35.3 61.7v5.1" fill="none" stroke="#000" stroke-width=".25"/>
<circle cx="35.3" cy="66.8" r=".49" fill="#000080"/>
<circle cx="35.3" cy="66.8" r=".49" fill="none" stroke="#000080" stroke-width=".21"/>
<path d="M35.3 61.7v5.1" fill="none" stroke="#000" stroke-width=".25"/>
<circle cx="35.3" cy="66.8" r=".49" fill="#000080"/>
<circle cx="35.3" cy="66.8" r=".49" fill="none" stroke="#000080" stroke-width=".21"/>
<path d="M35.3 61.7v5.1" fill="none" stroke="#000" stroke-width=".25"/>
<circle cx="35.3" cy="66.8" r=".49" fill="#000080"/>
<circle cx="35.3" cy="66.8" r=".49" fill="none" stroke="#000080" stroke-width=".21"/>
<path d="M35.3 61.7v5.1" fill="none" stroke="#000" stroke-width=".25"/>
<circle cx="35.3" cy="66.8" r=".49" fill="#000080"/>
<circle cx="35.3" cy="66.8" r=".49" fill="none" stroke="#000080" stroke-width=".21"/>
<circle cx="35.3" cy="66.8" r=".49" fill="#000080"/>
<circle cx="35.3" cy="66.8" r=".49" fill="none" stroke="#000080" stroke-width=".21"/>
<circle cx="35.3" cy="66.8" r=".49" fill="#000080"/>
<circle cx="35.3" cy="66.8" r=".49" fill="none" stroke="#000080" stroke-width=".21"/>
<circle cx="35.3" cy="66.8" r=".49" fill="#000080"/>
<circle cx="35.3" cy="66.8" r=".49" fill="none" stroke="#000080" stroke-width=".21"/>
<circle cx="35.3" cy="66.8" r=".49" fill="#000080"/>
<circle cx="35.3" cy="66.8" r=".49" fill="none" stroke="#000080" stroke-width=".21"/>
<circle cx="35.3" cy="66.8" r=".49" fill="#000080"/>
<circle cx="35.3" cy="66.8" r=".49" fill="none" stroke="#000080" stroke-width=".21"/>
<circle cx="35.3" cy="66.8" r=".49" fill="#000080"/>
<circle cx="35.3" cy="66.8" r=".49" fill="none" stroke="#000080" stroke-width=".21"/>
<path d="M25.1 153.2v5.2" fill="none" stroke="#000080" stroke-width=".25"/>
<circle cx="25.1" cy="153.2" r=".74" fill="#000080"/>
<circle cx="25.1" cy="153.2" r=".74" fill="none" stroke="#000080" stroke-width=".21"/>
<path d="M22.6 171.1h5M23.3 171.8h3.6M24.1 172.6h2M24.8 173.4h.6M25.1 168.5v2.6M63.3 171.1h5.1M64 171.8h3.6M64.8 172.6h2M65.6 173.4h.5M65.8 168.5v2.6" fill="none" stroke="#800000" stroke-width=".25"/>
<circle cx="65.8" cy="168.5" r=".49" fill="#000080"/>
<circle cx="65.8" cy="168.5" r=".49" fill="none" stroke="#000080" stroke-width=".21"/>
<path d="M170.1 171.1h2.6a1.25 1.25 0 0 1 1.2-1.3 1.25 1.25 0 0 1 1.3 1.3M175.2 171.1a1.25 1.25 0 0 1 1.3-1.3 1.25 1.25 0 0 1 1.2 1.3M177.8 171.1a1.25 1.25 0 0 1 1.2-1.3 1.25 1.25 0 0 1 1.3 1.3h2.5" fill="none" stroke="#000" stroke-width=".25"/>
<path d="M170.1 155.8h17.8v15.3h-5.1" fill="none" stroke="#000080" stroke-width=".25"/>
<circle cx="187.9" cy="171" r=".48" fill="#000080"/>
<circle cx="187.9" cy="171" r=".48" fill="none" stroke="#000080" stroke-width=".21"/>
<path d="M69.6 46.5v-7.6h-49.6v114.3h7.6" fill="none" stroke="#000080" stroke-width=".76"/>
<circle cx="69.6" cy="38.8" r=".75" fill="#000080"/>
<circle cx="69.6" cy="38.8" r=".75" fill="none" stroke="#000080" stroke-width=".21"/>
<path d="M185.4 49h2M185.4 59.2h2M187.4 46.7v4.6M187.4 56.9v4.6M188.4 49h2.1M188.4 46.7v4.6M188.4 56.9v4.6M188.4 59.2h2.1M59.5 132.9h2.5M69.6 132.9h2.6" fill="none" stroke="#000" stroke-width=".25"/>
<path d="M62 131.1h2.8v-.7h2v.7h2.8v.3h-7.6z" fill-rule="evenodd" fill="#00f"/>
<g fill="none" stroke="#00f" stroke-width=".25">
<path d="M62 131.1h2.8v-.7h2v.7h2.8v.3h-7.6z"/>
<circle cx="62.7" cy="132.9" r=".75"/>
<circle cx="68.9" cy="132.9" r=".74"/>
</g>
<g fill="none" stroke="#000080" stroke-width=".25">
<path d="M170.1 33.8h7.7M170.1 28.7h7.7M170.1 46.5h7.7M241.3 56.6h15.3M241.3 54.1h15.3M170.1 99.9h7.7M241.3 87.2h12a.74 .74 0 0 1 .8-.8 .74 .74 0 0 1 .7 .8M241.3 89.7h12a.74 .74 0 0 1 .8-.8 .74 .74 0 0 1 .7 .8M254.8 87.2h1.8M254.8 89.7h1.8M101.4 102.4h7.6M236.3 130.4h17a.74 .74 0 0 1 .8-.8 .74 .74 0 0 1 .7 .8"/>
<path d="M254.8 130.4h1.8M236.3 140.5h17a.74 .74 0 0 1 .8-.7 .74 .74 0 0 1 .7 .7M254.8 140.5h1.8"/>
</g>
<path d="M30.3 89.8h7.5v17.7h-7.5z" fill="#ffffb0"/>
<path d="M30.3 89.7h7.5v17.8h-7.5z" fill="none" stroke="#800000" stroke-width=".21"/>
<path d="M37.8 92.2h5.1M37.8 94.8h5.1M37.8 97.3h5.1M37.8 99.9h5.1M37.8 102.4h5.1M37.8 104.9h5.1" fill="none" stroke="#000" stroke-width=".25"/>
<path d="M42.9 97.3h12.8v2.6M42.9 94.8h7.6M42.9 99.9h7.6M42.9 102.4h7.6" fill="none" stroke="#000080" stroke-width=".25"/>
<path d="M55.7 99.9v2.5M53.1 102.4h5.1M53.8 103.2h3.6M54.6 103.9h2.1M55.4 104.7h.5" fill="none" stroke="#800000" stroke-width=".25"/>
<path d="M32.8 150.8h22.8v12.6h-22.8z" fill="#ffffb0"/>
<path d="M32.8 150.7h22.8v12.7h-22.8z" fill="none" stroke="#800000" stroke-width=".21"/>
<path d="M27.6 153.2h5.2M55.7 153.2h5M42.9 163.4v5.1" fill="none" stroke="#000" stroke-width=".25"/>
<circle cx="60.7" cy="153.2" r=".5" fill="#000080"/>
<circle cx="60.7" cy="153.2" r=".5" fill="none" stroke="#000080" stroke-width=".21"/>
<path d="M55.7 155.8h5" fill="none" stroke="#000" stroke-width=".25"/>
<circle cx="60.7" cy="153.2" r=".5" fill="#000080"/>
<circle cx="60.7" cy="153.2" r=".5" fill="none" stroke="#000080" stroke-width=".21"/>
<path d="M40.4 171.1h5.1M41.1 171.8h3.6M41.9 172.6h2M42.7 173.4h.5M42.9 168.5v2.6" fill="none" stroke="#800000" stroke-width=".25"/>
<path d="M25.1 163.4v5.1" fill="none" stroke="#000080" stroke-width=".25"/>
<path d="M58.5 73.2h4.5l-2.3 2.5zM58.5 75.7h4.5M60.7 69.3v3.9M60.7 75.7v3.8M63.8 76l1 1M63.8 73.9l1 1.1M65.3 76.8v.7h-.7zM65.3 74.7v.8h-.7zM65.8 64.3h2.6M68.4 63.2h5v2h-5zM73.4 64.3h2.6" fill="none" stroke="#000" stroke-width=".25"/>
<path d="M65.3 76.8v.7h-.7zM65.3 74.7v.8h-.7z" fill="#000"/>
<path d="M264.3 51.6h12.6v106.7h-12.6z" fill="#ffffb0"/>
<path d="M264.3 51.6h12.6v106.7h-12.6z" fill="none" stroke="#800000" stroke-width=".21"/>
<g fill="none" stroke="#000" stroke-width=".25">
<path d="M256.6 54.1h7.6M256.6 56.6h7.6M256.6 59.2h7.6M256.6 61.7h7.6M256.6 64.3h7.6M256.6 66.8h7.6M256.6 69.3h7.6M256.6 71.9h7.6M256.6 74.5h7.6M256.6 77h7.6M256.6 79.5h7.6M256.6 82.1h7.6"/>
<path d="M256.6 84.6h7.6M256.6 87.2h7.6M256.6 89.7h7.6M256.6 92.2h7.6M256.6 94.8h7.6M256.6 97.3h7.6M256.6 99.9h7.6M256.6 102.4h7.6M256.6 104.9h7.6M256.6 107.5h7.6M256.6 110h7.6M256.6 112.6h7.6"/>
<path d="M256.6 115.1h7.6M256.6 117.7h7.6M256.6 120.2h7.6M256.6 122.8h7.6M256.6 125.3h7.6M256.6 127.8h7.6M256.6 130.4h7.6M256.6 132.9h7.6M256.6 135.5h7.6M256.6 138h7.6M256.6 140.5h7.6M256.6 143.1h7.6"/>
<path d="M256.6 145.6h7.6M256.6 148.2h7.6M256.6 150.7h7.6M256.6 153.2h7.6M277 153.2h7.6M277 155.8h7.6M126.9 181.2v1.3"/>
</g>
<path d="M170.1 59.2h15.3M185.4 49h-7.6v7.6h-7.7" fill="none" stroke="#000080" stroke-width=".25"/>
<circle cx="126.8" cy="181.2" r=".49" fill="#000080"/>
<circle cx="126.8" cy="181.2" r=".49" fill="none" stroke="#000080" stroke-width=".21"/>
<path d="M126.9 185v1.3" fill="none" stroke="#000" stroke-width=".25"/>
<circle cx="126.8" cy="186.3" r=".49" fill="#000080"/>
<circle cx="126.8" cy="186.3" r=".49" fill="none" stroke="#000080" stroke-width=".21"/>
<path d="M124.6 184.3h4.6M124.6 183.3h4.6M126.9 182.5v.8M126.9 184.3v.7" fill="none" stroke="#000" stroke-width=".25"/>
<circle cx="126.8" cy="181.2" r=".49" fill="#000080"/>
<circle cx="126.8" cy="181.2" r=".49" fill="none" stroke="#000080" stroke-width=".21"/>
<circle cx="126.8" cy="186.3" r=".49" fill="#000080"/>
<circle cx="126.8" cy="186.3" r=".49" fill="none" stroke="#000080" stroke-width=".21"/>
<path d="M111.6 181.2h40.7M111.6 186.3h40.7" fill="none" stroke="#000080" stroke-width=".25"/>
<path d="M25.1 158.4v2M65.8 153.2v2.6M22.8 161.4h4.6M22.8 160.4h4.6M25.1 161.4v2" fill="none" stroke="#000" stroke-width=".25"/>
<circle cx="65.8" cy="153.2" r=".49" fill="#000080"/>
<circle cx="65.8" cy="153.2" r=".49" fill="none" stroke="#000080" stroke-width=".21"/>
<path d="M63.5 157.6h4.6v.8h-4.6zM63.5 159.4h4.6M65.8 155.8v1.8M65.8 159.4v4M66.6 156.3h1M67.1 155.8v1" fill="none" stroke="#000" stroke-width=".25"/>
<circle cx="65.8" cy="153.2" r=".49" fill="#000080"/>
<circle cx="65.8" cy="153.2" r=".49" fill="none" stroke="#000080" stroke-width=".21"/>
<path d="M67.1 49h2.5M67.1 51.6h2.5M69.6 48h5.1v2h-5.1zM69.6 50.5h5.1v2h-5.1zM74.7 49h2.6M74.7 51.6h2.6M60.7 125.3h2.6M63.3 124.3h5v2h-5zM68.4 125.3h2.5M68.4 120.2h2.5" fill="none" stroke="#000" stroke-width=".25"/>
<circle cx="70.9" cy="120.2" r=".48" fill="#000080"/>
<circle cx="70.9" cy="120.2" r=".48" fill="none" stroke="#000080" stroke-width=".21"/>
<path d="M63.3 119.2h5v2h-5zM60.7 120.2h2.6" fill="none" stroke="#000" stroke-width=".25"/>
<circle cx="70.9" cy="120.2" r=".48" fill="#000080"/>
<circle cx="70.9" cy="120.2" r=".48" fill="none" stroke="#000080" stroke-width=".21"/>
<path d="M109 120.2h-38.1v5.1" fill="none" stroke="#000080" stroke-width=".25"/>
<circle cx="70.9" cy="120.2" r=".48" fill="#000080"/>
<circle cx="70.9" cy="120.2" r=".48" fill="none" stroke="#000080" stroke-width=".21"/>
<path d="M133.2 185v1.3" fill="none" stroke="#000" stroke-width=".25"/>
<circle cx="133.2" cy="186.3" r=".49" fill="#000080"/>
<circle cx="133.2" cy="186.3" r=".49" fill="none" stroke="#000080" stroke-width=".21"/>
<path d="M133.2 181.2v1.3" fill="none" stroke="#000" stroke-width=".25"/>
<circle cx="133.2" cy="181.2" r=".49" fill="#000080"/>
<circle cx="133.2" cy="181.2" r=".49" fill="none" stroke="#000080" stroke-width=".21"/>
<path d="M130.9 183.3h4.6M130.9 184.3h4.6M133.2 182.5v.8M133.2 184.3v.7" fill="none" stroke="#000" stroke-width=".25"/>
<circle cx="133.2" cy="186.3" r=".49" fill="#000080"/>
<circle cx="133.2" cy="186.3" r=".49" fill="none" stroke="#000080" stroke-width=".21"/>
<circle cx="133.2" cy="181.2" r=".49" fill="#000080"/>
<circle cx="133.2" cy="181.2" r=".49" fill="none" stroke="#000080" stroke-width=".21"/>
<path d="M119.2 185v1.3" fill="none" stroke="#000" stroke-width=".25"/>
<circle cx="119.2" cy="186.3" r=".49" fill="#000080"/>
<circle cx="119.2" cy="186.3" r=".49" fill="none" stroke="#000080" stroke-width=".21"/>
<path d="M119.2 181.2v1.3" fill="none" stroke="#000" stroke-width=".25"/>
<circle cx="119.2" cy="181.2" r=".49" fill="#000080"/>
<circle cx="119.2" cy="181.2" r=".49" fill="none" stroke="#000080" stroke-width=".21"/>
<path d="M117 183.3h4.5M117 184.3h4.5M119.2 182.5v.8M119.2 184.3v.7" fill="none" stroke="#000" stroke-width=".25"/>
<circle cx="119.2" cy="186.3" r=".49" fill="#000080"/>
<circle cx="119.2" cy="186.3" r=".49" fill="none" stroke="#000080" stroke-width=".21"/>
<circle cx="119.2" cy="181.2" r=".49" fill="#000080"/>
<circle cx="119.2" cy="181.2" r=".49" fill="none" stroke="#000080" stroke-width=".21"/>
<path d="M106.5 135.5v1.2M106.5 139.3v1.2M150 183.3h4.6M150 184.3h4.6M152.3 181.2v2.1M152.3 184.3v2" fill="none" stroke="#000" stroke-width=".25"/>
<circle cx="106.5" cy="135.4" r=".49" fill="#000080"/>
<circle cx="106.5" cy="135.4" r=".49" fill="none" stroke="#000080" stroke-width=".21"/>
<path d="M104.2 137.5h4.6M104.2 138.5h4.6M106.5 136.7v.8M106.5 138.5v.8" fill="none" stroke="#000" stroke-width=".25"/>
<circle cx="106.5" cy="135.4" r=".49" fill="#000080"/>
<circle cx="106.5" cy="135.4" r=".49" fill="none" stroke="#000080" stroke-width=".21"/>
<path d="M92.5 106.2h2.1M92.5 116.4h2.1M94.6 103.9v4.6M94.6 114.1v4.6M95.6 106.2h2M95.6 103.9v4.6M95.6 114.1v4.6M95.6 116.4h2M87.5 130.4h2M89.5 128.1v4.6M90.5 130.4h2M90.5 128.1v4.6" fill="none" stroke="#000" stroke-width=".25"/>
<path d="M84.9 132.9h24.1" fill="none" stroke="#000080" stroke-width=".25"/>
<circle cx="84.9" cy="132.9" r=".48" fill="#000080"/>
<circle cx="84.9" cy="132.9" r=".48" fill="none" stroke="#000080" stroke-width=".21"/>
<path d="M87.5 130.4h-2.6v2.5" fill="none" stroke="#000080" stroke-width=".25"/>
<circle cx="84.9" cy="132.9" r=".48" fill="#000080"/>
<circle cx="84.9" cy="132.9" r=".48" fill="none" stroke="#000080" stroke-width=".21"/>
<path d="M146 185v1.3" fill="none" stroke="#000" stroke-width=".25"/>
<circle cx="145.9" cy="186.3" r=".49" fill="#000080"/>
<circle cx="145.9" cy="186.3" r=".49" fill="none" stroke="#000080" stroke-width=".21"/>
<path d="M146 181.2v1.3" fill="none" stroke="#000" stroke-width=".25"/>
<circle cx="145.9" cy="181.2" r=".49" fill="#000080"/>
<circle cx="145.9" cy="181.2" r=".49" fill="none" stroke="#000080" stroke-width=".21"/>
<path d="M143.7 183.3h4.5M143.7 184.3h4.5M146 182.5v.8M146 184.3v.7" fill="none" stroke="#000" stroke-width=".25"/>
<circle cx="145.9" cy="186.3" r=".49" fill="#000080"/>
<circle cx="145.9" cy="186.3" r=".49" fill="none" stroke="#000080" stroke-width=".21"/>
<circle cx="145.9" cy="181.2" r=".49" fill="#000080"/>
<circle cx="145.9" cy="181.2" r=".49" fill="none" stroke="#000080" stroke-width=".21"/>
<path d="M88.7 125.3h2.6M91.3 124.3h5v2h-5zM96.3 125.3h2.6M139.6 185v1.3" fill="none" stroke="#000" stroke-width=".25"/>
<circle cx="139.6" cy="186.3" r=".48" fill="#000080"/>
<circle cx="139.6" cy="186.3" r=".48" fill="none" stroke="#000080" stroke-width=".21"/>
<path d="M139.6 181.2v1.3" fill="none" stroke="#000" stroke-width=".25"/>
<circle cx="139.6" cy="181.2" r=".48" fill="#000080"/>
<circle cx="139.6" cy="181.2" r=".48" fill="none" stroke="#000080" stroke-width=".21"/>
<path d="M137.3 183.3h4.6M137.3 184.3h4.6M139.6 182.5v.8M139.6 184.3v.7" fill="none" stroke="#000" stroke-width=".25"/>
<circle cx="139.6" cy="186.3" r=".48" fill="#000080"/>
<circle cx="139.6" cy="186.3" r=".48" fill="none" stroke="#000080" stroke-width=".21"/>
<circle cx="139.6" cy="181.2" r=".48" fill="#000080"/>
<circle cx="139.6" cy="181.2" r=".48" fill="none" stroke="#000080" stroke-width=".21"/>
<path d="M72.4 157.8h4.6M72.4 158.9h4.6M74.7 155.8v2M74.7 158.9v2" fill="none" stroke="#000" stroke-width=".25"/>
<path d="M60.7 153.2v2.6" fill="none" stroke="#000080" stroke-width=".25"/>
<circle cx="60.7" cy="153.2" r=".5" fill="#000080"/>
<circle cx="60.7" cy="153.2" r=".5" fill="none" stroke="#000080" stroke-width=".21"/>
<path d="M60.7 153.2h5.1" fill="none" stroke="#000080" stroke-width=".25"/>
<circle cx="60.7" cy="153.2" r=".5" fill="#000080"/>
<circle cx="60.7" cy="153.2" r=".5" fill="none" stroke="#000080" stroke-width=".21"/>
<circle cx="65.8" cy="153.2" r=".49" fill="#000080"/>
<circle cx="65.8" cy="153.2" r=".49" fill="none" stroke="#000080" stroke-width=".21"/>
<path d="M65.8 153.2h8.9v2.6" fill="none" stroke="#000080" stroke-width=".25"/>
<circle cx="65.8" cy="153.2" r=".49" fill="#000080"/>
<circle cx="65.8" cy="153.2" r=".49" fill="none" stroke="#000080" stroke-width=".21"/>
<path d="M74.7 160.9v7.6h-8.9" fill="none" stroke="#000080" stroke-width=".25"/>
<circle cx="74.7" cy="168.5" r=".48" fill="#000080"/>
<circle cx="74.7" cy="168.5" r=".48" fill="none" stroke="#000080" stroke-width=".21"/>
<circle cx="65.8" cy="168.5" r=".49" fill="#000080"/>
<circle cx="65.8" cy="168.5" r=".49" fill="none" stroke="#000080" stroke-width=".21"/>
<path d="M65.8 163.4v5.1" fill="none" stroke="#000080" stroke-width=".25"/>
<circle cx="65.8" cy="168.5" r=".49" fill="#000080"/>
<circle cx="65.8" cy="168.5" r=".49" fill="none" stroke="#000080" stroke-width=".21"/>
<path d="M72.2 171.1h5.1M72.9 171.8h3.6M73.7 172.6h2M74.5 173.4h.5M74.7 168.5v2.6" fill="none" stroke="#800000" stroke-width=".25"/>
<circle cx="74.7" cy="168.5" r=".48" fill="#000080"/>
<circle cx="74.7" cy="168.5" r=".48" fill="none" stroke="#000080" stroke-width=".21"/>
<path d="M82.6 38.9h2v5h-2zM83.6 36.3v2.6M83.6 43.9v2.6" fill="none" stroke="#000" stroke-width=".25"/>
<use href="#words"/>
</svg>
